VERSION 5.8 ;
BUSBITCHARS "[]" ;
DIVIDERCHAR "/" ;
UNITS
    DATABASE MICRONS 1000 ;
END UNITS

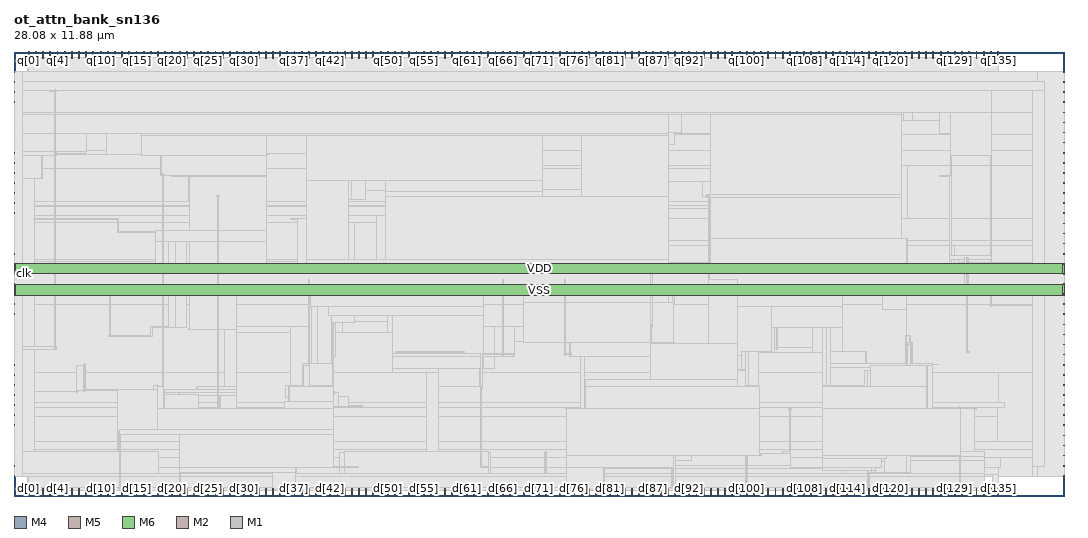
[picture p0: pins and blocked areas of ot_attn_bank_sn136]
MACRO ot_attn_bank_sn136
  FOREIGN ot_attn_bank_sn136 0 0 ;
  CLASS BLOCK ;
  SIZE 28.08 BY 11.88 ;
  PIN clk
    DIRECTION INPUT ;
    USE SIGNAL ;
    PORT
      LAYER M4 ;
        RECT  0 5.928 0.192 5.952 ;
    END
  END clk
  PIN d[0]
    DIRECTION INPUT ;
    USE SIGNAL ;
    PORT
      LAYER M5 ;
        RECT  0.384 0 0.408 0.192 ;
    END
  END d[0]
  PIN d[100]
    DIRECTION INPUT ;
    USE SIGNAL ;
    PORT
      LAYER M5 ;
        RECT  19.584 0 19.608 0.192 ;
    END
  END d[100]
  PIN d[101]
    DIRECTION INPUT ;
    USE SIGNAL ;
    PORT
      LAYER M5 ;
        RECT  19.776 0 19.8 0.192 ;
    END
  END d[101]
  PIN d[102]
    DIRECTION INPUT ;
    USE SIGNAL ;
    PORT
      LAYER M5 ;
        RECT  19.968 0 19.992 0.192 ;
    END
  END d[102]
  PIN d[103]
    DIRECTION INPUT ;
    USE SIGNAL ;
    PORT
      LAYER M5 ;
        RECT  20.16 0 20.184 0.192 ;
    END
  END d[103]
  PIN d[104]
    DIRECTION INPUT ;
    USE SIGNAL ;
    PORT
      LAYER M5 ;
        RECT  20.352 0 20.376 0.192 ;
    END
  END d[104]
  PIN d[105]
    DIRECTION INPUT ;
    USE SIGNAL ;
    PORT
      LAYER M5 ;
        RECT  20.544 0 20.568 0.192 ;
    END
  END d[105]
  PIN d[106]
    DIRECTION INPUT ;
    USE SIGNAL ;
    PORT
      LAYER M5 ;
        RECT  20.736 0 20.76 0.192 ;
    END
  END d[106]
  PIN d[107]
    DIRECTION INPUT ;
    USE SIGNAL ;
    PORT
      LAYER M5 ;
        RECT  20.928 0 20.952 0.192 ;
    END
  END d[107]
  PIN d[108]
    DIRECTION INPUT ;
    USE SIGNAL ;
    PORT
      LAYER M5 ;
        RECT  21.12 0 21.144 0.192 ;
    END
  END d[108]
  PIN d[109]
    DIRECTION INPUT ;
    USE SIGNAL ;
    PORT
      LAYER M5 ;
        RECT  21.312 0 21.336 0.192 ;
    END
  END d[109]
  PIN d[10]
    DIRECTION INPUT ;
    USE SIGNAL ;
    PORT
      LAYER M5 ;
        RECT  2.304 0 2.328 0.192 ;
    END
  END d[10]
  PIN d[110]
    DIRECTION INPUT ;
    USE SIGNAL ;
    PORT
      LAYER M5 ;
        RECT  21.504 0 21.528 0.192 ;
    END
  END d[110]
  PIN d[111]
    DIRECTION INPUT ;
    USE SIGNAL ;
    PORT
      LAYER M5 ;
        RECT  21.696 0 21.72 0.192 ;
    END
  END d[111]
  PIN d[112]
    DIRECTION INPUT ;
    USE SIGNAL ;
    PORT
      LAYER M5 ;
        RECT  21.888 0 21.912 0.192 ;
    END
  END d[112]
  PIN d[113]
    DIRECTION INPUT ;
    USE SIGNAL ;
    PORT
      LAYER M5 ;
        RECT  22.08 0 22.104 0.192 ;
    END
  END d[113]
  PIN d[114]
    DIRECTION INPUT ;
    USE SIGNAL ;
    PORT
      LAYER M5 ;
        RECT  22.272 0 22.296 0.192 ;
    END
  END d[114]
  PIN d[115]
    DIRECTION INPUT ;
    USE SIGNAL ;
    PORT
      LAYER M5 ;
        RECT  22.464 0 22.488 0.192 ;
    END
  END d[115]
  PIN d[116]
    DIRECTION INPUT ;
    USE SIGNAL ;
    PORT
      LAYER M5 ;
        RECT  22.656 0 22.68 0.192 ;
    END
  END d[116]
  PIN d[117]
    DIRECTION INPUT ;
    USE SIGNAL ;
    PORT
      LAYER M5 ;
        RECT  22.848 0 22.872 0.192 ;
    END
  END d[117]
  PIN d[118]
    DIRECTION INPUT ;
    USE SIGNAL ;
    PORT
      LAYER M5 ;
        RECT  23.04 0 23.064 0.192 ;
    END
  END d[118]
  PIN d[119]
    DIRECTION INPUT ;
    USE SIGNAL ;
    PORT
      LAYER M5 ;
        RECT  23.232 0 23.256 0.192 ;
    END
  END d[119]
  PIN d[11]
    DIRECTION INPUT ;
    USE SIGNAL ;
    PORT
      LAYER M5 ;
        RECT  2.496 0 2.52 0.192 ;
    END
  END d[11]
  PIN d[120]
    DIRECTION INPUT ;
    USE SIGNAL ;
    PORT
      LAYER M5 ;
        RECT  23.424 0 23.448 0.192 ;
    END
  END d[120]
  PIN d[121]
    DIRECTION INPUT ;
    USE SIGNAL ;
    PORT
      LAYER M5 ;
        RECT  23.616 0 23.64 0.192 ;
    END
  END d[121]
  PIN d[122]
    DIRECTION INPUT ;
    USE SIGNAL ;
    PORT
      LAYER M5 ;
        RECT  23.808 0 23.832 0.192 ;
    END
  END d[122]
  PIN d[123]
    DIRECTION INPUT ;
    USE SIGNAL ;
    PORT
      LAYER M5 ;
        RECT  24 0 24.024 0.192 ;
    END
  END d[123]
  PIN d[124]
    DIRECTION INPUT ;
    USE SIGNAL ;
    PORT
      LAYER M5 ;
        RECT  24.192 0 24.216 0.192 ;
    END
  END d[124]
  PIN d[125]
    DIRECTION INPUT ;
    USE SIGNAL ;
    PORT
      LAYER M5 ;
        RECT  24.384 0 24.408 0.192 ;
    END
  END d[125]
  PIN d[126]
    DIRECTION INPUT ;
    USE SIGNAL ;
    PORT
      LAYER M5 ;
        RECT  24.576 0 24.6 0.192 ;
    END
  END d[126]
  PIN d[127]
    DIRECTION INPUT ;
    USE SIGNAL ;
    PORT
      LAYER M5 ;
        RECT  24.768 0 24.792 0.192 ;
    END
  END d[127]
  PIN d[128]
    DIRECTION INPUT ;
    USE SIGNAL ;
    PORT
      LAYER M5 ;
        RECT  24.96 0 24.984 0.192 ;
    END
  END d[128]
  PIN d[129]
    DIRECTION INPUT ;
    USE SIGNAL ;
    PORT
      LAYER M5 ;
        RECT  25.152 0 25.176 0.192 ;
    END
  END d[129]
  PIN d[12]
    DIRECTION INPUT ;
    USE SIGNAL ;
    PORT
      LAYER M5 ;
        RECT  2.688 0 2.712 0.192 ;
    END
  END d[12]
  PIN d[130]
    DIRECTION INPUT ;
    USE SIGNAL ;
    PORT
      LAYER M5 ;
        RECT  25.344 0 25.368 0.192 ;
    END
  END d[130]
  PIN d[131]
    DIRECTION INPUT ;
    USE SIGNAL ;
    PORT
      LAYER M5 ;
        RECT  25.536 0 25.56 0.192 ;
    END
  END d[131]
  PIN d[132]
    DIRECTION INPUT ;
    USE SIGNAL ;
    PORT
      LAYER M5 ;
        RECT  25.728 0 25.752 0.192 ;
    END
  END d[132]
  PIN d[133]
    DIRECTION INPUT ;
    USE SIGNAL ;
    PORT
      LAYER M5 ;
        RECT  25.92 0 25.944 0.192 ;
    END
  END d[133]
  PIN d[134]
    DIRECTION INPUT ;
    USE SIGNAL ;
    PORT
      LAYER M5 ;
        RECT  26.112 0 26.136 0.192 ;
    END
  END d[134]
  PIN d[135]
    DIRECTION INPUT ;
    USE SIGNAL ;
    PORT
      LAYER M5 ;
        RECT  26.304 0 26.328 0.192 ;
    END
  END d[135]
  PIN d[13]
    DIRECTION INPUT ;
    USE SIGNAL ;
    PORT
      LAYER M5 ;
        RECT  2.88 0 2.904 0.192 ;
    END
  END d[13]
  PIN d[14]
    DIRECTION INPUT ;
    USE SIGNAL ;
    PORT
      LAYER M5 ;
        RECT  3.072 0 3.096 0.192 ;
    END
  END d[14]
  PIN d[15]
    DIRECTION INPUT ;
    USE SIGNAL ;
    PORT
      LAYER M5 ;
        RECT  3.264 0 3.288 0.192 ;
    END
  END d[15]
  PIN d[16]
    DIRECTION INPUT ;
    USE SIGNAL ;
    PORT
      LAYER M5 ;
        RECT  3.456 0 3.48 0.192 ;
    END
  END d[16]
  PIN d[17]
    DIRECTION INPUT ;
    USE SIGNAL ;
    PORT
      LAYER M5 ;
        RECT  3.648 0 3.672 0.192 ;
    END
  END d[17]
  PIN d[18]
    DIRECTION INPUT ;
    USE SIGNAL ;
    PORT
      LAYER M5 ;
        RECT  3.84 0 3.864 0.192 ;
    END
  END d[18]
  PIN d[19]
    DIRECTION INPUT ;
    USE SIGNAL ;
    PORT
      LAYER M5 ;
        RECT  4.032 0 4.056 0.192 ;
    END
  END d[19]
  PIN d[1]
    DIRECTION INPUT ;
    USE SIGNAL ;
    PORT
      LAYER M5 ;
        RECT  0.576 0 0.6 0.192 ;
    END
  END d[1]
  PIN d[20]
    DIRECTION INPUT ;
    USE SIGNAL ;
    PORT
      LAYER M5 ;
        RECT  4.224 0 4.248 0.192 ;
    END
  END d[20]
  PIN d[21]
    DIRECTION INPUT ;
    USE SIGNAL ;
    PORT
      LAYER M5 ;
        RECT  4.416 0 4.44 0.192 ;
    END
  END d[21]
  PIN d[22]
    DIRECTION INPUT ;
    USE SIGNAL ;
    PORT
      LAYER M5 ;
        RECT  4.608 0 4.632 0.192 ;
    END
  END d[22]
  PIN d[23]
    DIRECTION INPUT ;
    USE SIGNAL ;
    PORT
      LAYER M5 ;
        RECT  4.8 0 4.824 0.192 ;
    END
  END d[23]
  PIN d[24]
    DIRECTION INPUT ;
    USE SIGNAL ;
    PORT
      LAYER M5 ;
        RECT  4.992 0 5.016 0.192 ;
    END
  END d[24]
  PIN d[25]
    DIRECTION INPUT ;
    USE SIGNAL ;
    PORT
      LAYER M5 ;
        RECT  5.184 0 5.208 0.192 ;
    END
  END d[25]
  PIN d[26]
    DIRECTION INPUT ;
    USE SIGNAL ;
    PORT
      LAYER M5 ;
        RECT  5.376 0 5.4 0.192 ;
    END
  END d[26]
  PIN d[27]
    DIRECTION INPUT ;
    USE SIGNAL ;
    PORT
      LAYER M5 ;
        RECT  5.568 0 5.592 0.192 ;
    END
  END d[27]
  PIN d[28]
    DIRECTION INPUT ;
    USE SIGNAL ;
    PORT
      LAYER M5 ;
        RECT  5.76 0 5.784 0.192 ;
    END
  END d[28]
  PIN d[29]
    DIRECTION INPUT ;
    USE SIGNAL ;
    PORT
      LAYER M5 ;
        RECT  5.952 0 5.976 0.192 ;
    END
  END d[29]
  PIN d[2]
    DIRECTION INPUT ;
    USE SIGNAL ;
    PORT
      LAYER M5 ;
        RECT  0.768 0 0.792 0.192 ;
    END
  END d[2]
  PIN d[30]
    DIRECTION INPUT ;
    USE SIGNAL ;
    PORT
      LAYER M5 ;
        RECT  6.144 0 6.168 0.192 ;
    END
  END d[30]
  PIN d[31]
    DIRECTION INPUT ;
    USE SIGNAL ;
    PORT
      LAYER M5 ;
        RECT  6.336 0 6.36 0.192 ;
    END
  END d[31]
  PIN d[32]
    DIRECTION INPUT ;
    USE SIGNAL ;
    PORT
      LAYER M5 ;
        RECT  6.528 0 6.552 0.192 ;
    END
  END d[32]
  PIN d[33]
    DIRECTION INPUT ;
    USE SIGNAL ;
    PORT
      LAYER M5 ;
        RECT  6.72 0 6.744 0.192 ;
    END
  END d[33]
  PIN d[34]
    DIRECTION INPUT ;
    USE SIGNAL ;
    PORT
      LAYER M5 ;
        RECT  6.912 0 6.936 0.192 ;
    END
  END d[34]
  PIN d[35]
    DIRECTION INPUT ;
    USE SIGNAL ;
    PORT
      LAYER M5 ;
        RECT  7.104 0 7.128 0.192 ;
    END
  END d[35]
  PIN d[36]
    DIRECTION INPUT ;
    USE SIGNAL ;
    PORT
      LAYER M5 ;
        RECT  7.296 0 7.32 0.192 ;
    END
  END d[36]
  PIN d[37]
    DIRECTION INPUT ;
    USE SIGNAL ;
    PORT
      LAYER M5 ;
        RECT  7.488 0 7.512 0.192 ;
    END
  END d[37]
  PIN d[38]
    DIRECTION INPUT ;
    USE SIGNAL ;
    PORT
      LAYER M5 ;
        RECT  7.68 0 7.704 0.192 ;
    END
  END d[38]
  PIN d[39]
    DIRECTION INPUT ;
    USE SIGNAL ;
    PORT
      LAYER M5 ;
        RECT  7.872 0 7.896 0.192 ;
    END
  END d[39]
  PIN d[3]
    DIRECTION INPUT ;
    USE SIGNAL ;
    PORT
      LAYER M5 ;
        RECT  0.96 0 0.984 0.192 ;
    END
  END d[3]
  PIN d[40]
    DIRECTION INPUT ;
    USE SIGNAL ;
    PORT
      LAYER M5 ;
        RECT  8.064 0 8.088 0.192 ;
    END
  END d[40]
  PIN d[41]
    DIRECTION INPUT ;
    USE SIGNAL ;
    PORT
      LAYER M5 ;
        RECT  8.256 0 8.28 0.192 ;
    END
  END d[41]
  PIN d[42]
    DIRECTION INPUT ;
    USE SIGNAL ;
    PORT
      LAYER M5 ;
        RECT  8.448 0 8.472 0.192 ;
    END
  END d[42]
  PIN d[43]
    DIRECTION INPUT ;
    USE SIGNAL ;
    PORT
      LAYER M5 ;
        RECT  8.64 0 8.664 0.192 ;
    END
  END d[43]
  PIN d[44]
    DIRECTION INPUT ;
    USE SIGNAL ;
    PORT
      LAYER M5 ;
        RECT  8.832 0 8.856 0.192 ;
    END
  END d[44]
  PIN d[45]
    DIRECTION INPUT ;
    USE SIGNAL ;
    PORT
      LAYER M5 ;
        RECT  9.024 0 9.048 0.192 ;
    END
  END d[45]
  PIN d[46]
    DIRECTION INPUT ;
    USE SIGNAL ;
    PORT
      LAYER M5 ;
        RECT  9.216 0 9.24 0.192 ;
    END
  END d[46]
  PIN d[47]
    DIRECTION INPUT ;
    USE SIGNAL ;
    PORT
      LAYER M5 ;
        RECT  9.408 0 9.432 0.192 ;
    END
  END d[47]
  PIN d[48]
    DIRECTION INPUT ;
    USE SIGNAL ;
    PORT
      LAYER M5 ;
        RECT  9.6 0 9.624 0.192 ;
    END
  END d[48]
  PIN d[49]
    DIRECTION INPUT ;
    USE SIGNAL ;
    PORT
      LAYER M5 ;
        RECT  9.792 0 9.816 0.192 ;
    END
  END d[49]
  PIN d[4]
    DIRECTION INPUT ;
    USE SIGNAL ;
    PORT
      LAYER M5 ;
        RECT  1.152 0 1.176 0.192 ;
    END
  END d[4]
  PIN d[50]
    DIRECTION INPUT ;
    USE SIGNAL ;
    PORT
      LAYER M5 ;
        RECT  9.984 0 10.008 0.192 ;
    END
  END d[50]
  PIN d[51]
    DIRECTION INPUT ;
    USE SIGNAL ;
    PORT
      LAYER M5 ;
        RECT  10.176 0 10.2 0.192 ;
    END
  END d[51]
  PIN d[52]
    DIRECTION INPUT ;
    USE SIGNAL ;
    PORT
      LAYER M5 ;
        RECT  10.368 0 10.392 0.192 ;
    END
  END d[52]
  PIN d[53]
    DIRECTION INPUT ;
    USE SIGNAL ;
    PORT
      LAYER M5 ;
        RECT  10.56 0 10.584 0.192 ;
    END
  END d[53]
  PIN d[54]
    DIRECTION INPUT ;
    USE SIGNAL ;
    PORT
      LAYER M5 ;
        RECT  10.752 0 10.776 0.192 ;
    END
  END d[54]
  PIN d[55]
    DIRECTION INPUT ;
    USE SIGNAL ;
    PORT
      LAYER M5 ;
        RECT  10.944 0 10.968 0.192 ;
    END
  END d[55]
  PIN d[56]
    DIRECTION INPUT ;
    USE SIGNAL ;
    PORT
      LAYER M5 ;
        RECT  11.136 0 11.16 0.192 ;
    END
  END d[56]
  PIN d[57]
    DIRECTION INPUT ;
    USE SIGNAL ;
    PORT
      LAYER M5 ;
        RECT  11.328 0 11.352 0.192 ;
    END
  END d[57]
  PIN d[58]
    DIRECTION INPUT ;
    USE SIGNAL ;
    PORT
      LAYER M5 ;
        RECT  11.52 0 11.544 0.192 ;
    END
  END d[58]
  PIN d[59]
    DIRECTION INPUT ;
    USE SIGNAL ;
    PORT
      LAYER M5 ;
        RECT  11.712 0 11.736 0.192 ;
    END
  END d[59]
  PIN d[5]
    DIRECTION INPUT ;
    USE SIGNAL ;
    PORT
      LAYER M5 ;
        RECT  1.344 0 1.368 0.192 ;
    END
  END d[5]
  PIN d[60]
    DIRECTION INPUT ;
    USE SIGNAL ;
    PORT
      LAYER M5 ;
        RECT  11.904 0 11.928 0.192 ;
    END
  END d[60]
  PIN d[61]
    DIRECTION INPUT ;
    USE SIGNAL ;
    PORT
      LAYER M5 ;
        RECT  12.096 0 12.12 0.192 ;
    END
  END d[61]
  PIN d[62]
    DIRECTION INPUT ;
    USE SIGNAL ;
    PORT
      LAYER M5 ;
        RECT  12.288 0 12.312 0.192 ;
    END
  END d[62]
  PIN d[63]
    DIRECTION INPUT ;
    USE SIGNAL ;
    PORT
      LAYER M5 ;
        RECT  12.48 0 12.504 0.192 ;
    END
  END d[63]
  PIN d[64]
    DIRECTION INPUT ;
    USE SIGNAL ;
    PORT
      LAYER M5 ;
        RECT  12.672 0 12.696 0.192 ;
    END
  END d[64]
  PIN d[65]
    DIRECTION INPUT ;
    USE SIGNAL ;
    PORT
      LAYER M5 ;
        RECT  12.864 0 12.888 0.192 ;
    END
  END d[65]
  PIN d[66]
    DIRECTION INPUT ;
    USE SIGNAL ;
    PORT
      LAYER M5 ;
        RECT  13.056 0 13.08 0.192 ;
    END
  END d[66]
  PIN d[67]
    DIRECTION INPUT ;
    USE SIGNAL ;
    PORT
      LAYER M5 ;
        RECT  13.248 0 13.272 0.192 ;
    END
  END d[67]
  PIN d[68]
    DIRECTION INPUT ;
    USE SIGNAL ;
    PORT
      LAYER M5 ;
        RECT  13.44 0 13.464 0.192 ;
    END
  END d[68]
  PIN d[69]
    DIRECTION INPUT ;
    USE SIGNAL ;
    PORT
      LAYER M5 ;
        RECT  13.632 0 13.656 0.192 ;
    END
  END d[69]
  PIN d[6]
    DIRECTION INPUT ;
    USE SIGNAL ;
    PORT
      LAYER M5 ;
        RECT  1.536 0 1.56 0.192 ;
    END
  END d[6]
  PIN d[70]
    DIRECTION INPUT ;
    USE SIGNAL ;
    PORT
      LAYER M5 ;
        RECT  13.824 0 13.848 0.192 ;
    END
  END d[70]
  PIN d[71]
    DIRECTION INPUT ;
    USE SIGNAL ;
    PORT
      LAYER M5 ;
        RECT  14.016 0 14.04 0.192 ;
    END
  END d[71]
  PIN d[72]
    DIRECTION INPUT ;
    USE SIGNAL ;
    PORT
      LAYER M5 ;
        RECT  14.208 0 14.232 0.192 ;
    END
  END d[72]
  PIN d[73]
    DIRECTION INPUT ;
    USE SIGNAL ;
    PORT
      LAYER M5 ;
        RECT  14.4 0 14.424 0.192 ;
    END
  END d[73]
  PIN d[74]
    DIRECTION INPUT ;
    USE SIGNAL ;
    PORT
      LAYER M5 ;
        RECT  14.592 0 14.616 0.192 ;
    END
  END d[74]
  PIN d[75]
    DIRECTION INPUT ;
    USE SIGNAL ;
    PORT
      LAYER M5 ;
        RECT  14.784 0 14.808 0.192 ;
    END
  END d[75]
  PIN d[76]
    DIRECTION INPUT ;
    USE SIGNAL ;
    PORT
      LAYER M5 ;
        RECT  14.976 0 15 0.192 ;
    END
  END d[76]
  PIN d[77]
    DIRECTION INPUT ;
    USE SIGNAL ;
    PORT
      LAYER M5 ;
        RECT  15.168 0 15.192 0.192 ;
    END
  END d[77]
  PIN d[78]
    DIRECTION INPUT ;
    USE SIGNAL ;
    PORT
      LAYER M5 ;
        RECT  15.36 0 15.384 0.192 ;
    END
  END d[78]
  PIN d[79]
    DIRECTION INPUT ;
    USE SIGNAL ;
    PORT
      LAYER M5 ;
        RECT  15.552 0 15.576 0.192 ;
    END
  END d[79]
  PIN d[7]
    DIRECTION INPUT ;
    USE SIGNAL ;
    PORT
      LAYER M5 ;
        RECT  1.728 0 1.752 0.192 ;
    END
  END d[7]
  PIN d[80]
    DIRECTION INPUT ;
    USE SIGNAL ;
    PORT
      LAYER M5 ;
        RECT  15.744 0 15.768 0.192 ;
    END
  END d[80]
  PIN d[81]
    DIRECTION INPUT ;
    USE SIGNAL ;
    PORT
      LAYER M5 ;
        RECT  15.936 0 15.96 0.192 ;
    END
  END d[81]
  PIN d[82]
    DIRECTION INPUT ;
    USE SIGNAL ;
    PORT
      LAYER M5 ;
        RECT  16.128 0 16.152 0.192 ;
    END
  END d[82]
  PIN d[83]
    DIRECTION INPUT ;
    USE SIGNAL ;
    PORT
      LAYER M5 ;
        RECT  16.32 0 16.344 0.192 ;
    END
  END d[83]
  PIN d[84]
    DIRECTION INPUT ;
    USE SIGNAL ;
    PORT
      LAYER M5 ;
        RECT  16.512 0 16.536 0.192 ;
    END
  END d[84]
  PIN d[85]
    DIRECTION INPUT ;
    USE SIGNAL ;
    PORT
      LAYER M5 ;
        RECT  16.704 0 16.728 0.192 ;
    END
  END d[85]
  PIN d[86]
    DIRECTION INPUT ;
    USE SIGNAL ;
    PORT
      LAYER M5 ;
        RECT  16.896 0 16.92 0.192 ;
    END
  END d[86]
  PIN d[87]
    DIRECTION INPUT ;
    USE SIGNAL ;
    PORT
      LAYER M5 ;
        RECT  17.088 0 17.112 0.192 ;
    END
  END d[87]
  PIN d[88]
    DIRECTION INPUT ;
    USE SIGNAL ;
    PORT
      LAYER M5 ;
        RECT  17.28 0 17.304 0.192 ;
    END
  END d[88]
  PIN d[89]
    DIRECTION INPUT ;
    USE SIGNAL ;
    PORT
      LAYER M5 ;
        RECT  17.472 0 17.496 0.192 ;
    END
  END d[89]
  PIN d[8]
    DIRECTION INPUT ;
    USE SIGNAL ;
    PORT
      LAYER M5 ;
        RECT  1.92 0 1.944 0.192 ;
    END
  END d[8]
  PIN d[90]
    DIRECTION INPUT ;
    USE SIGNAL ;
    PORT
      LAYER M5 ;
        RECT  17.664 0 17.688 0.192 ;
    END
  END d[90]
  PIN d[91]
    DIRECTION INPUT ;
    USE SIGNAL ;
    PORT
      LAYER M5 ;
        RECT  17.856 0 17.88 0.192 ;
    END
  END d[91]
  PIN d[92]
    DIRECTION INPUT ;
    USE SIGNAL ;
    PORT
      LAYER M5 ;
        RECT  18.048 0 18.072 0.192 ;
    END
  END d[92]
  PIN d[93]
    DIRECTION INPUT ;
    USE SIGNAL ;
    PORT
      LAYER M5 ;
        RECT  18.24 0 18.264 0.192 ;
    END
  END d[93]
  PIN d[94]
    DIRECTION INPUT ;
    USE SIGNAL ;
    PORT
      LAYER M5 ;
        RECT  18.432 0 18.456 0.192 ;
    END
  END d[94]
  PIN d[95]
    DIRECTION INPUT ;
    USE SIGNAL ;
    PORT
      LAYER M5 ;
        RECT  18.624 0 18.648 0.192 ;
    END
  END d[95]
  PIN d[96]
    DIRECTION INPUT ;
    USE SIGNAL ;
    PORT
      LAYER M5 ;
        RECT  18.816 0 18.84 0.192 ;
    END
  END d[96]
  PIN d[97]
    DIRECTION INPUT ;
    USE SIGNAL ;
    PORT
      LAYER M5 ;
        RECT  19.008 0 19.032 0.192 ;
    END
  END d[97]
  PIN d[98]
    DIRECTION INPUT ;
    USE SIGNAL ;
    PORT
      LAYER M5 ;
        RECT  19.2 0 19.224 0.192 ;
    END
  END d[98]
  PIN d[99]
    DIRECTION INPUT ;
    USE SIGNAL ;
    PORT
      LAYER M5 ;
        RECT  19.392 0 19.416 0.192 ;
    END
  END d[99]
  PIN d[9]
    DIRECTION INPUT ;
    USE SIGNAL ;
    PORT
      LAYER M5 ;
        RECT  2.112 0 2.136 0.192 ;
    END
  END d[9]
  PIN q[0]
    DIRECTION OUTPUT ;
    USE SIGNAL ;
    PORT
      LAYER M5 ;
        RECT  0.384 11.688 0.408 11.88 ;
    END
  END q[0]
  PIN q[100]
    DIRECTION OUTPUT ;
    USE SIGNAL ;
    PORT
      LAYER M5 ;
        RECT  19.584 11.688 19.608 11.88 ;
    END
  END q[100]
  PIN q[101]
    DIRECTION OUTPUT ;
    USE SIGNAL ;
    PORT
      LAYER M5 ;
        RECT  19.776 11.688 19.8 11.88 ;
    END
  END q[101]
  PIN q[102]
    DIRECTION OUTPUT ;
    USE SIGNAL ;
    PORT
      LAYER M5 ;
        RECT  19.968 11.688 19.992 11.88 ;
    END
  END q[102]
  PIN q[103]
    DIRECTION OUTPUT ;
    USE SIGNAL ;
    PORT
      LAYER M5 ;
        RECT  20.16 11.688 20.184 11.88 ;
    END
  END q[103]
  PIN q[104]
    DIRECTION OUTPUT ;
    USE SIGNAL ;
    PORT
      LAYER M5 ;
        RECT  20.352 11.688 20.376 11.88 ;
    END
  END q[104]
  PIN q[105]
    DIRECTION OUTPUT ;
    USE SIGNAL ;
    PORT
      LAYER M5 ;
        RECT  20.544 11.688 20.568 11.88 ;
    END
  END q[105]
  PIN q[106]
    DIRECTION OUTPUT ;
    USE SIGNAL ;
    PORT
      LAYER M5 ;
        RECT  20.736 11.688 20.76 11.88 ;
    END
  END q[106]
  PIN q[107]
    DIRECTION OUTPUT ;
    USE SIGNAL ;
    PORT
      LAYER M5 ;
        RECT  20.928 11.688 20.952 11.88 ;
    END
  END q[107]
  PIN q[108]
    DIRECTION OUTPUT ;
    USE SIGNAL ;
    PORT
      LAYER M5 ;
        RECT  21.12 11.688 21.144 11.88 ;
    END
  END q[108]
  PIN q[109]
    DIRECTION OUTPUT ;
    USE SIGNAL ;
    PORT
      LAYER M5 ;
        RECT  21.312 11.688 21.336 11.88 ;
    END
  END q[109]
  PIN q[10]
    DIRECTION OUTPUT ;
    USE SIGNAL ;
    PORT
      LAYER M5 ;
        RECT  2.304 11.688 2.328 11.88 ;
    END
  END q[10]
  PIN q[110]
    DIRECTION OUTPUT ;
    USE SIGNAL ;
    PORT
      LAYER M5 ;
        RECT  21.504 11.688 21.528 11.88 ;
    END
  END q[110]
  PIN q[111]
    DIRECTION OUTPUT ;
    USE SIGNAL ;
    PORT
      LAYER M5 ;
        RECT  21.696 11.688 21.72 11.88 ;
    END
  END q[111]
  PIN q[112]
    DIRECTION OUTPUT ;
    USE SIGNAL ;
    PORT
      LAYER M5 ;
        RECT  21.888 11.688 21.912 11.88 ;
    END
  END q[112]
  PIN q[113]
    DIRECTION OUTPUT ;
    USE SIGNAL ;
    PORT
      LAYER M5 ;
        RECT  22.08 11.688 22.104 11.88 ;
    END
  END q[113]
  PIN q[114]
    DIRECTION OUTPUT ;
    USE SIGNAL ;
    PORT
      LAYER M5 ;
        RECT  22.272 11.688 22.296 11.88 ;
    END
  END q[114]
  PIN q[115]
    DIRECTION OUTPUT ;
    USE SIGNAL ;
    PORT
      LAYER M5 ;
        RECT  22.464 11.688 22.488 11.88 ;
    END
  END q[115]
  PIN q[116]
    DIRECTION OUTPUT ;
    USE SIGNAL ;
    PORT
      LAYER M5 ;
        RECT  22.656 11.688 22.68 11.88 ;
    END
  END q[116]
  PIN q[117]
    DIRECTION OUTPUT ;
    USE SIGNAL ;
    PORT
      LAYER M5 ;
        RECT  22.848 11.688 22.872 11.88 ;
    END
  END q[117]
  PIN q[118]
    DIRECTION OUTPUT ;
    USE SIGNAL ;
    PORT
      LAYER M5 ;
        RECT  23.04 11.688 23.064 11.88 ;
    END
  END q[118]
  PIN q[119]
    DIRECTION OUTPUT ;
    USE SIGNAL ;
    PORT
      LAYER M5 ;
        RECT  23.232 11.688 23.256 11.88 ;
    END
  END q[119]
  PIN q[11]
    DIRECTION OUTPUT ;
    USE SIGNAL ;
    PORT
      LAYER M5 ;
        RECT  2.496 11.688 2.52 11.88 ;
    END
  END q[11]
  PIN q[120]
    DIRECTION OUTPUT ;
    USE SIGNAL ;
    PORT
      LAYER M5 ;
        RECT  23.424 11.688 23.448 11.88 ;
    END
  END q[120]
  PIN q[121]
    DIRECTION OUTPUT ;
    USE SIGNAL ;
    PORT
      LAYER M5 ;
        RECT  23.616 11.688 23.64 11.88 ;
    END
  END q[121]
  PIN q[122]
    DIRECTION OUTPUT ;
    USE SIGNAL ;
    PORT
      LAYER M5 ;
        RECT  23.808 11.688 23.832 11.88 ;
    END
  END q[122]
  PIN q[123]
    DIRECTION OUTPUT ;
    USE SIGNAL ;
    PORT
      LAYER M5 ;
        RECT  24 11.688 24.024 11.88 ;
    END
  END q[123]
  PIN q[124]
    DIRECTION OUTPUT ;
    USE SIGNAL ;
    PORT
      LAYER M5 ;
        RECT  24.192 11.688 24.216 11.88 ;
    END
  END q[124]
  PIN q[125]
    DIRECTION OUTPUT ;
    USE SIGNAL ;
    PORT
      LAYER M5 ;
        RECT  24.384 11.688 24.408 11.88 ;
    END
  END q[125]
  PIN q[126]
    DIRECTION OUTPUT ;
    USE SIGNAL ;
    PORT
      LAYER M5 ;
        RECT  24.576 11.688 24.6 11.88 ;
    END
  END q[126]
  PIN q[127]
    DIRECTION OUTPUT ;
    USE SIGNAL ;
    PORT
      LAYER M5 ;
        RECT  24.768 11.688 24.792 11.88 ;
    END
  END q[127]
  PIN q[128]
    DIRECTION OUTPUT ;
    USE SIGNAL ;
    PORT
      LAYER M5 ;
        RECT  24.96 11.688 24.984 11.88 ;
    END
  END q[128]
  PIN q[129]
    DIRECTION OUTPUT ;
    USE SIGNAL ;
    PORT
      LAYER M5 ;
        RECT  25.152 11.688 25.176 11.88 ;
    END
  END q[129]
  PIN q[12]
    DIRECTION OUTPUT ;
    USE SIGNAL ;
    PORT
      LAYER M5 ;
        RECT  2.688 11.688 2.712 11.88 ;
    END
  END q[12]
  PIN q[130]
    DIRECTION OUTPUT ;
    USE SIGNAL ;
    PORT
      LAYER M5 ;
        RECT  25.344 11.688 25.368 11.88 ;
    END
  END q[130]
  PIN q[131]
    DIRECTION OUTPUT ;
    USE SIGNAL ;
    PORT
      LAYER M5 ;
        RECT  25.536 11.688 25.56 11.88 ;
    END
  END q[131]
  PIN q[132]
    DIRECTION OUTPUT ;
    USE SIGNAL ;
    PORT
      LAYER M5 ;
        RECT  25.728 11.688 25.752 11.88 ;
    END
  END q[132]
  PIN q[133]
    DIRECTION OUTPUT ;
    USE SIGNAL ;
    PORT
      LAYER M5 ;
        RECT  25.92 11.688 25.944 11.88 ;
    END
  END q[133]
  PIN q[134]
    DIRECTION OUTPUT ;
    USE SIGNAL ;
    PORT
      LAYER M5 ;
        RECT  26.112 11.688 26.136 11.88 ;
    END
  END q[134]
  PIN q[135]
    DIRECTION OUTPUT ;
    USE SIGNAL ;
    PORT
      LAYER M5 ;
        RECT  26.304 11.688 26.328 11.88 ;
    END
  END q[135]
  PIN q[13]
    DIRECTION OUTPUT ;
    USE SIGNAL ;
    PORT
      LAYER M5 ;
        RECT  2.88 11.688 2.904 11.88 ;
    END
  END q[13]
  PIN q[14]
    DIRECTION OUTPUT ;
    USE SIGNAL ;
    PORT
      LAYER M5 ;
        RECT  3.072 11.688 3.096 11.88 ;
    END
  END q[14]
  PIN q[15]
    DIRECTION OUTPUT ;
    USE SIGNAL ;
    PORT
      LAYER M5 ;
        RECT  3.264 11.688 3.288 11.88 ;
    END
  END q[15]
  PIN q[16]
    DIRECTION OUTPUT ;
    USE SIGNAL ;
    PORT
      LAYER M5 ;
        RECT  3.456 11.688 3.48 11.88 ;
    END
  END q[16]
  PIN q[17]
    DIRECTION OUTPUT ;
    USE SIGNAL ;
    PORT
      LAYER M5 ;
        RECT  3.648 11.688 3.672 11.88 ;
    END
  END q[17]
  PIN q[18]
    DIRECTION OUTPUT ;
    USE SIGNAL ;
    PORT
      LAYER M5 ;
        RECT  3.84 11.688 3.864 11.88 ;
    END
  END q[18]
  PIN q[19]
    DIRECTION OUTPUT ;
    USE SIGNAL ;
    PORT
      LAYER M5 ;
        RECT  4.032 11.688 4.056 11.88 ;
    END
  END q[19]
  PIN q[1]
    DIRECTION OUTPUT ;
    USE SIGNAL ;
    PORT
      LAYER M5 ;
        RECT  0.576 11.688 0.6 11.88 ;
    END
  END q[1]
  PIN q[20]
    DIRECTION OUTPUT ;
    USE SIGNAL ;
    PORT
      LAYER M5 ;
        RECT  4.224 11.688 4.248 11.88 ;
    END
  END q[20]
  PIN q[21]
    DIRECTION OUTPUT ;
    USE SIGNAL ;
    PORT
      LAYER M5 ;
        RECT  4.416 11.688 4.44 11.88 ;
    END
  END q[21]
  PIN q[22]
    DIRECTION OUTPUT ;
    USE SIGNAL ;
    PORT
      LAYER M5 ;
        RECT  4.608 11.688 4.632 11.88 ;
    END
  END q[22]
  PIN q[23]
    DIRECTION OUTPUT ;
    USE SIGNAL ;
    PORT
      LAYER M5 ;
        RECT  4.8 11.688 4.824 11.88 ;
    END
  END q[23]
  PIN q[24]
    DIRECTION OUTPUT ;
    USE SIGNAL ;
    PORT
      LAYER M5 ;
        RECT  4.992 11.688 5.016 11.88 ;
    END
  END q[24]
  PIN q[25]
    DIRECTION OUTPUT ;
    USE SIGNAL ;
    PORT
      LAYER M5 ;
        RECT  5.184 11.688 5.208 11.88 ;
    END
  END q[25]
  PIN q[26]
    DIRECTION OUTPUT ;
    USE SIGNAL ;
    PORT
      LAYER M5 ;
        RECT  5.376 11.688 5.4 11.88 ;
    END
  END q[26]
  PIN q[27]
    DIRECTION OUTPUT ;
    USE SIGNAL ;
    PORT
      LAYER M5 ;
        RECT  5.568 11.688 5.592 11.88 ;
    END
  END q[27]
  PIN q[28]
    DIRECTION OUTPUT ;
    USE SIGNAL ;
    PORT
      LAYER M5 ;
        RECT  5.76 11.688 5.784 11.88 ;
    END
  END q[28]
  PIN q[29]
    DIRECTION OUTPUT ;
    USE SIGNAL ;
    PORT
      LAYER M5 ;
        RECT  5.952 11.688 5.976 11.88 ;
    END
  END q[29]
  PIN q[2]
    DIRECTION OUTPUT ;
    USE SIGNAL ;
    PORT
      LAYER M5 ;
        RECT  0.768 11.688 0.792 11.88 ;
    END
  END q[2]
  PIN q[30]
    DIRECTION OUTPUT ;
    USE SIGNAL ;
    PORT
      LAYER M5 ;
        RECT  6.144 11.688 6.168 11.88 ;
    END
  END q[30]
  PIN q[31]
    DIRECTION OUTPUT ;
    USE SIGNAL ;
    PORT
      LAYER M5 ;
        RECT  6.336 11.688 6.36 11.88 ;
    END
  END q[31]
  PIN q[32]
    DIRECTION OUTPUT ;
    USE SIGNAL ;
    PORT
      LAYER M5 ;
        RECT  6.528 11.688 6.552 11.88 ;
    END
  END q[32]
  PIN q[33]
    DIRECTION OUTPUT ;
    USE SIGNAL ;
    PORT
      LAYER M5 ;
        RECT  6.72 11.688 6.744 11.88 ;
    END
  END q[33]
  PIN q[34]
    DIRECTION OUTPUT ;
    USE SIGNAL ;
    PORT
      LAYER M5 ;
        RECT  6.912 11.688 6.936 11.88 ;
    END
  END q[34]
  PIN q[35]
    DIRECTION OUTPUT ;
    USE SIGNAL ;
    PORT
      LAYER M5 ;
        RECT  7.104 11.688 7.128 11.88 ;
    END
  END q[35]
  PIN q[36]
    DIRECTION OUTPUT ;
    USE SIGNAL ;
    PORT
      LAYER M5 ;
        RECT  7.296 11.688 7.32 11.88 ;
    END
  END q[36]
  PIN q[37]
    DIRECTION OUTPUT ;
    USE SIGNAL ;
    PORT
      LAYER M5 ;
        RECT  7.488 11.688 7.512 11.88 ;
    END
  END q[37]
  PIN q[38]
    DIRECTION OUTPUT ;
    USE SIGNAL ;
    PORT
      LAYER M5 ;
        RECT  7.68 11.688 7.704 11.88 ;
    END
  END q[38]
  PIN q[39]
    DIRECTION OUTPUT ;
    USE SIGNAL ;
    PORT
      LAYER M5 ;
        RECT  7.872 11.688 7.896 11.88 ;
    END
  END q[39]
  PIN q[3]
    DIRECTION OUTPUT ;
    USE SIGNAL ;
    PORT
      LAYER M5 ;
        RECT  0.96 11.688 0.984 11.88 ;
    END
  END q[3]
  PIN q[40]
    DIRECTION OUTPUT ;
    USE SIGNAL ;
    PORT
      LAYER M5 ;
        RECT  8.064 11.688 8.088 11.88 ;
    END
  END q[40]
  PIN q[41]
    DIRECTION OUTPUT ;
    USE SIGNAL ;
    PORT
      LAYER M5 ;
        RECT  8.256 11.688 8.28 11.88 ;
    END
  END q[41]
  PIN q[42]
    DIRECTION OUTPUT ;
    USE SIGNAL ;
    PORT
      LAYER M5 ;
        RECT  8.448 11.688 8.472 11.88 ;
    END
  END q[42]
  PIN q[43]
    DIRECTION OUTPUT ;
    USE SIGNAL ;
    PORT
      LAYER M5 ;
        RECT  8.64 11.688 8.664 11.88 ;
    END
  END q[43]
  PIN q[44]
    DIRECTION OUTPUT ;
    USE SIGNAL ;
    PORT
      LAYER M5 ;
        RECT  8.832 11.688 8.856 11.88 ;
    END
  END q[44]
  PIN q[45]
    DIRECTION OUTPUT ;
    USE SIGNAL ;
    PORT
      LAYER M5 ;
        RECT  9.024 11.688 9.048 11.88 ;
    END
  END q[45]
  PIN q[46]
    DIRECTION OUTPUT ;
    USE SIGNAL ;
    PORT
      LAYER M5 ;
        RECT  9.216 11.688 9.24 11.88 ;
    END
  END q[46]
  PIN q[47]
    DIRECTION OUTPUT ;
    USE SIGNAL ;
    PORT
      LAYER M5 ;
        RECT  9.408 11.688 9.432 11.88 ;
    END
  END q[47]
  PIN q[48]
    DIRECTION OUTPUT ;
    USE SIGNAL ;
    PORT
      LAYER M5 ;
        RECT  9.6 11.688 9.624 11.88 ;
    END
  END q[48]
  PIN q[49]
    DIRECTION OUTPUT ;
    USE SIGNAL ;
    PORT
      LAYER M5 ;
        RECT  9.792 11.688 9.816 11.88 ;
    END
  END q[49]
  PIN q[4]
    DIRECTION OUTPUT ;
    USE SIGNAL ;
    PORT
      LAYER M5 ;
        RECT  1.152 11.688 1.176 11.88 ;
    END
  END q[4]
  PIN q[50]
    DIRECTION OUTPUT ;
    USE SIGNAL ;
    PORT
      LAYER M5 ;
        RECT  9.984 11.688 10.008 11.88 ;
    END
  END q[50]
  PIN q[51]
    DIRECTION OUTPUT ;
    USE SIGNAL ;
    PORT
      LAYER M5 ;
        RECT  10.176 11.688 10.2 11.88 ;
    END
  END q[51]
  PIN q[52]
    DIRECTION OUTPUT ;
    USE SIGNAL ;
    PORT
      LAYER M5 ;
        RECT  10.368 11.688 10.392 11.88 ;
    END
  END q[52]
  PIN q[53]
    DIRECTION OUTPUT ;
    USE SIGNAL ;
    PORT
      LAYER M5 ;
        RECT  10.56 11.688 10.584 11.88 ;
    END
  END q[53]
  PIN q[54]
    DIRECTION OUTPUT ;
    USE SIGNAL ;
    PORT
      LAYER M5 ;
        RECT  10.752 11.688 10.776 11.88 ;
    END
  END q[54]
  PIN q[55]
    DIRECTION OUTPUT ;
    USE SIGNAL ;
    PORT
      LAYER M5 ;
        RECT  10.944 11.688 10.968 11.88 ;
    END
  END q[55]
  PIN q[56]
    DIRECTION OUTPUT ;
    USE SIGNAL ;
    PORT
      LAYER M5 ;
        RECT  11.136 11.688 11.16 11.88 ;
    END
  END q[56]
  PIN q[57]
    DIRECTION OUTPUT ;
    USE SIGNAL ;
    PORT
      LAYER M5 ;
        RECT  11.328 11.688 11.352 11.88 ;
    END
  END q[57]
  PIN q[58]
    DIRECTION OUTPUT ;
    USE SIGNAL ;
    PORT
      LAYER M5 ;
        RECT  11.52 11.688 11.544 11.88 ;
    END
  END q[58]
  PIN q[59]
    DIRECTION OUTPUT ;
    USE SIGNAL ;
    PORT
      LAYER M5 ;
        RECT  11.712 11.688 11.736 11.88 ;
    END
  END q[59]
  PIN q[5]
    DIRECTION OUTPUT ;
    USE SIGNAL ;
    PORT
      LAYER M5 ;
        RECT  1.344 11.688 1.368 11.88 ;
    END
  END q[5]
  PIN q[60]
    DIRECTION OUTPUT ;
    USE SIGNAL ;
    PORT
      LAYER M5 ;
        RECT  11.904 11.688 11.928 11.88 ;
    END
  END q[60]
  PIN q[61]
    DIRECTION OUTPUT ;
    USE SIGNAL ;
    PORT
      LAYER M5 ;
        RECT  12.096 11.688 12.12 11.88 ;
    END
  END q[61]
  PIN q[62]
    DIRECTION OUTPUT ;
    USE SIGNAL ;
    PORT
      LAYER M5 ;
        RECT  12.288 11.688 12.312 11.88 ;
    END
  END q[62]
  PIN q[63]
    DIRECTION OUTPUT ;
    USE SIGNAL ;
    PORT
      LAYER M5 ;
        RECT  12.48 11.688 12.504 11.88 ;
    END
  END q[63]
  PIN q[64]
    DIRECTION OUTPUT ;
    USE SIGNAL ;
    PORT
      LAYER M5 ;
        RECT  12.672 11.688 12.696 11.88 ;
    END
  END q[64]
  PIN q[65]
    DIRECTION OUTPUT ;
    USE SIGNAL ;
    PORT
      LAYER M5 ;
        RECT  12.864 11.688 12.888 11.88 ;
    END
  END q[65]
  PIN q[66]
    DIRECTION OUTPUT ;
    USE SIGNAL ;
    PORT
      LAYER M5 ;
        RECT  13.056 11.688 13.08 11.88 ;
    END
  END q[66]
  PIN q[67]
    DIRECTION OUTPUT ;
    USE SIGNAL ;
    PORT
      LAYER M5 ;
        RECT  13.248 11.688 13.272 11.88 ;
    END
  END q[67]
  PIN q[68]
    DIRECTION OUTPUT ;
    USE SIGNAL ;
    PORT
      LAYER M5 ;
        RECT  13.44 11.688 13.464 11.88 ;
    END
  END q[68]
  PIN q[69]
    DIRECTION OUTPUT ;
    USE SIGNAL ;
    PORT
      LAYER M5 ;
        RECT  13.632 11.688 13.656 11.88 ;
    END
  END q[69]
  PIN q[6]
    DIRECTION OUTPUT ;
    USE SIGNAL ;
    PORT
      LAYER M5 ;
        RECT  1.536 11.688 1.56 11.88 ;
    END
  END q[6]
  PIN q[70]
    DIRECTION OUTPUT ;
    USE SIGNAL ;
    PORT
      LAYER M5 ;
        RECT  13.824 11.688 13.848 11.88 ;
    END
  END q[70]
  PIN q[71]
    DIRECTION OUTPUT ;
    USE SIGNAL ;
    PORT
      LAYER M5 ;
        RECT  14.016 11.688 14.04 11.88 ;
    END
  END q[71]
  PIN q[72]
    DIRECTION OUTPUT ;
    USE SIGNAL ;
    PORT
      LAYER M5 ;
        RECT  14.208 11.688 14.232 11.88 ;
    END
  END q[72]
  PIN q[73]
    DIRECTION OUTPUT ;
    USE SIGNAL ;
    PORT
      LAYER M5 ;
        RECT  14.4 11.688 14.424 11.88 ;
    END
  END q[73]
  PIN q[74]
    DIRECTION OUTPUT ;
    USE SIGNAL ;
    PORT
      LAYER M5 ;
        RECT  14.592 11.688 14.616 11.88 ;
    END
  END q[74]
  PIN q[75]
    DIRECTION OUTPUT ;
    USE SIGNAL ;
    PORT
      LAYER M5 ;
        RECT  14.784 11.688 14.808 11.88 ;
    END
  END q[75]
  PIN q[76]
    DIRECTION OUTPUT ;
    USE SIGNAL ;
    PORT
      LAYER M5 ;
        RECT  14.976 11.688 15 11.88 ;
    END
  END q[76]
  PIN q[77]
    DIRECTION OUTPUT ;
    USE SIGNAL ;
    PORT
      LAYER M5 ;
        RECT  15.168 11.688 15.192 11.88 ;
    END
  END q[77]
  PIN q[78]
    DIRECTION OUTPUT ;
    USE SIGNAL ;
    PORT
      LAYER M5 ;
        RECT  15.36 11.688 15.384 11.88 ;
    END
  END q[78]
  PIN q[79]
    DIRECTION OUTPUT ;
    USE SIGNAL ;
    PORT
      LAYER M5 ;
        RECT  15.552 11.688 15.576 11.88 ;
    END
  END q[79]
  PIN q[7]
    DIRECTION OUTPUT ;
    USE SIGNAL ;
    PORT
      LAYER M5 ;
        RECT  1.728 11.688 1.752 11.88 ;
    END
  END q[7]
  PIN q[80]
    DIRECTION OUTPUT ;
    USE SIGNAL ;
    PORT
      LAYER M5 ;
        RECT  15.744 11.688 15.768 11.88 ;
    END
  END q[80]
  PIN q[81]
    DIRECTION OUTPUT ;
    USE SIGNAL ;
    PORT
      LAYER M5 ;
        RECT  15.936 11.688 15.96 11.88 ;
    END
  END q[81]
  PIN q[82]
    DIRECTION OUTPUT ;
    USE SIGNAL ;
    PORT
      LAYER M5 ;
        RECT  16.128 11.688 16.152 11.88 ;
    END
  END q[82]
  PIN q[83]
    DIRECTION OUTPUT ;
    USE SIGNAL ;
    PORT
      LAYER M5 ;
        RECT  16.32 11.688 16.344 11.88 ;
    END
  END q[83]
  PIN q[84]
    DIRECTION OUTPUT ;
    USE SIGNAL ;
    PORT
      LAYER M5 ;
        RECT  16.512 11.688 16.536 11.88 ;
    END
  END q[84]
  PIN q[85]
    DIRECTION OUTPUT ;
    USE SIGNAL ;
    PORT
      LAYER M5 ;
        RECT  16.704 11.688 16.728 11.88 ;
    END
  END q[85]
  PIN q[86]
    DIRECTION OUTPUT ;
    USE SIGNAL ;
    PORT
      LAYER M5 ;
        RECT  16.896 11.688 16.92 11.88 ;
    END
  END q[86]
  PIN q[87]
    DIRECTION OUTPUT ;
    USE SIGNAL ;
    PORT
      LAYER M5 ;
        RECT  17.088 11.688 17.112 11.88 ;
    END
  END q[87]
  PIN q[88]
    DIRECTION OUTPUT ;
    USE SIGNAL ;
    PORT
      LAYER M5 ;
        RECT  17.28 11.688 17.304 11.88 ;
    END
  END q[88]
  PIN q[89]
    DIRECTION OUTPUT ;
    USE SIGNAL ;
    PORT
      LAYER M5 ;
        RECT  17.472 11.688 17.496 11.88 ;
    END
  END q[89]
  PIN q[8]
    DIRECTION OUTPUT ;
    USE SIGNAL ;
    PORT
      LAYER M5 ;
        RECT  1.92 11.688 1.944 11.88 ;
    END
  END q[8]
  PIN q[90]
    DIRECTION OUTPUT ;
    USE SIGNAL ;
    PORT
      LAYER M5 ;
        RECT  17.664 11.688 17.688 11.88 ;
    END
  END q[90]
  PIN q[91]
    DIRECTION OUTPUT ;
    USE SIGNAL ;
    PORT
      LAYER M5 ;
        RECT  17.856 11.688 17.88 11.88 ;
    END
  END q[91]
  PIN q[92]
    DIRECTION OUTPUT ;
    USE SIGNAL ;
    PORT
      LAYER M5 ;
        RECT  18.048 11.688 18.072 11.88 ;
    END
  END q[92]
  PIN q[93]
    DIRECTION OUTPUT ;
    USE SIGNAL ;
    PORT
      LAYER M5 ;
        RECT  18.24 11.688 18.264 11.88 ;
    END
  END q[93]
  PIN q[94]
    DIRECTION OUTPUT ;
    USE SIGNAL ;
    PORT
      LAYER M5 ;
        RECT  18.432 11.688 18.456 11.88 ;
    END
  END q[94]
  PIN q[95]
    DIRECTION OUTPUT ;
    USE SIGNAL ;
    PORT
      LAYER M5 ;
        RECT  18.624 11.688 18.648 11.88 ;
    END
  END q[95]
  PIN q[96]
    DIRECTION OUTPUT ;
    USE SIGNAL ;
    PORT
      LAYER M5 ;
        RECT  18.816 11.688 18.84 11.88 ;
    END
  END q[96]
  PIN q[97]
    DIRECTION OUTPUT ;
    USE SIGNAL ;
    PORT
      LAYER M5 ;
        RECT  19.008 11.688 19.032 11.88 ;
    END
  END q[97]
  PIN q[98]
    DIRECTION OUTPUT ;
    USE SIGNAL ;
    PORT
      LAYER M5 ;
        RECT  19.2 11.688 19.224 11.88 ;
    END
  END q[98]
  PIN q[99]
    DIRECTION OUTPUT ;
    USE SIGNAL ;
    PORT
      LAYER M5 ;
        RECT  19.392 11.688 19.416 11.88 ;
    END
  END q[99]
  PIN q[9]
    DIRECTION OUTPUT ;
    USE SIGNAL ;
    PORT
      LAYER M5 ;
        RECT  2.112 11.688 2.136 11.88 ;
    END
  END q[9]
  PIN VDD
    DIRECTION INOUT ;
    USE POWER ;
    PORT
      LAYER M6 ;
        RECT  28.048 5.94 28.08 6.228 ;
        RECT  0 5.94 0.032 6.228 ;
        RECT  0 5.94 28.08 6.228 ;
      LAYER M2 ;
        RECT  28.062 11.061 28.08 11.079 ;
        RECT  0 11.061 0.018 11.079 ;
        RECT  28.062 10.521 28.08 10.539 ;
        RECT  0 10.521 0.018 10.539 ;
        RECT  28.062 9.981 28.08 9.999 ;
        RECT  0 9.981 0.018 9.999 ;
        RECT  28.062 9.441 28.08 9.459 ;
        RECT  0 9.441 0.018 9.459 ;
        RECT  28.062 8.901 28.08 8.919 ;
        RECT  0 8.901 0.018 8.919 ;
        RECT  28.062 8.361 28.08 8.379 ;
        RECT  0 8.361 0.018 8.379 ;
        RECT  28.062 7.821 28.08 7.839 ;
        RECT  0 7.821 0.018 7.839 ;
        RECT  28.062 7.281 28.08 7.299 ;
        RECT  0 7.281 0.018 7.299 ;
        RECT  28.062 6.741 28.08 6.759 ;
        RECT  0 6.741 0.018 6.759 ;
        RECT  28.062 6.201 28.08 6.219 ;
        RECT  0 6.201 0.018 6.219 ;
        RECT  28.062 5.661 28.08 5.679 ;
        RECT  0 5.661 0.018 5.679 ;
        RECT  28.062 5.121 28.08 5.139 ;
        RECT  0 5.121 0.018 5.139 ;
        RECT  28.062 4.581 28.08 4.599 ;
        RECT  0 4.581 0.018 4.599 ;
        RECT  28.062 4.041 28.08 4.059 ;
        RECT  0 4.041 0.018 4.059 ;
        RECT  28.062 3.501 28.08 3.519 ;
        RECT  0 3.501 0.018 3.519 ;
        RECT  28.062 2.961 28.08 2.979 ;
        RECT  0 2.961 0.018 2.979 ;
        RECT  28.062 2.421 28.08 2.439 ;
        RECT  0 2.421 0.018 2.439 ;
        RECT  28.062 1.881 28.08 1.899 ;
        RECT  0 1.881 0.018 1.899 ;
        RECT  28.062 1.341 28.08 1.359 ;
        RECT  0 1.341 0.018 1.359 ;
        RECT  28.062 0.801 28.08 0.819 ;
        RECT  0 0.801 0.018 0.819 ;
      LAYER M1 ;
        RECT  28.062 11.061 28.08 11.079 ;
        RECT  0 11.061 0.018 11.079 ;
        RECT  28.062 10.521 28.08 10.539 ;
        RECT  0 10.521 0.018 10.539 ;
        RECT  28.062 9.981 28.08 9.999 ;
        RECT  0 9.981 0.018 9.999 ;
        RECT  28.062 9.441 28.08 9.459 ;
        RECT  0 9.441 0.018 9.459 ;
        RECT  28.062 8.901 28.08 8.919 ;
        RECT  0 8.901 0.018 8.919 ;
        RECT  28.062 8.361 28.08 8.379 ;
        RECT  0 8.361 0.018 8.379 ;
        RECT  28.062 7.821 28.08 7.839 ;
        RECT  0 7.821 0.018 7.839 ;
        RECT  28.062 7.281 28.08 7.299 ;
        RECT  0 7.281 0.018 7.299 ;
        RECT  28.062 6.741 28.08 6.759 ;
        RECT  0 6.741 0.018 6.759 ;
        RECT  28.062 6.201 28.08 6.219 ;
        RECT  0 6.201 0.018 6.219 ;
        RECT  28.062 5.661 28.08 5.679 ;
        RECT  0 5.661 0.018 5.679 ;
        RECT  28.062 5.121 28.08 5.139 ;
        RECT  0 5.121 0.018 5.139 ;
        RECT  28.062 4.581 28.08 4.599 ;
        RECT  0 4.581 0.018 4.599 ;
        RECT  28.062 4.041 28.08 4.059 ;
        RECT  0 4.041 0.018 4.059 ;
        RECT  28.062 3.501 28.08 3.519 ;
        RECT  0 3.501 0.018 3.519 ;
        RECT  28.062 2.961 28.08 2.979 ;
        RECT  0 2.961 0.018 2.979 ;
        RECT  28.062 2.421 28.08 2.439 ;
        RECT  0 2.421 0.018 2.439 ;
        RECT  28.062 1.881 28.08 1.899 ;
        RECT  0 1.881 0.018 1.899 ;
        RECT  28.062 1.341 28.08 1.359 ;
        RECT  0 1.341 0.018 1.359 ;
        RECT  28.062 0.801 28.08 0.819 ;
        RECT  0 0.801 0.018 0.819 ;
    END
  END VDD
  PIN VSS
    DIRECTION INOUT ;
    USE GROUND ;
    PORT
      LAYER M6 ;
        RECT  28.048 5.364 28.08 5.652 ;
        RECT  0 5.364 0.032 5.652 ;
        RECT  0 5.364 28.08 5.652 ;
      LAYER M2 ;
        RECT  28.062 11.331 28.08 11.349 ;
        RECT  0 11.331 0.018 11.349 ;
        RECT  28.062 10.791 28.08 10.809 ;
        RECT  0 10.791 0.018 10.809 ;
        RECT  28.062 10.251 28.08 10.269 ;
        RECT  0 10.251 0.018 10.269 ;
        RECT  28.062 9.711 28.08 9.729 ;
        RECT  0 9.711 0.018 9.729 ;
        RECT  28.062 9.171 28.08 9.189 ;
        RECT  0 9.171 0.018 9.189 ;
        RECT  28.062 8.631 28.08 8.649 ;
        RECT  0 8.631 0.018 8.649 ;
        RECT  28.062 8.091 28.08 8.109 ;
        RECT  0 8.091 0.018 8.109 ;
        RECT  28.062 7.551 28.08 7.569 ;
        RECT  0 7.551 0.018 7.569 ;
        RECT  28.062 7.011 28.08 7.029 ;
        RECT  0 7.011 0.018 7.029 ;
        RECT  28.062 6.471 28.08 6.489 ;
        RECT  0 6.471 0.018 6.489 ;
        RECT  28.062 5.931 28.08 5.949 ;
        RECT  0 5.931 0.018 5.949 ;
        RECT  28.062 5.391 28.08 5.409 ;
        RECT  0 5.391 0.018 5.409 ;
        RECT  28.062 4.851 28.08 4.869 ;
        RECT  0 4.851 0.018 4.869 ;
        RECT  28.062 4.311 28.08 4.329 ;
        RECT  0 4.311 0.018 4.329 ;
        RECT  28.062 3.771 28.08 3.789 ;
        RECT  0 3.771 0.018 3.789 ;
        RECT  28.062 3.231 28.08 3.249 ;
        RECT  0 3.231 0.018 3.249 ;
        RECT  28.062 2.691 28.08 2.709 ;
        RECT  0 2.691 0.018 2.709 ;
        RECT  28.062 2.151 28.08 2.169 ;
        RECT  0 2.151 0.018 2.169 ;
        RECT  28.062 1.611 28.08 1.629 ;
        RECT  0 1.611 0.018 1.629 ;
        RECT  28.062 1.071 28.08 1.089 ;
        RECT  0 1.071 0.018 1.089 ;
        RECT  28.062 0.531 28.08 0.549 ;
        RECT  0 0.531 0.018 0.549 ;
      LAYER M1 ;
        RECT  28.062 11.331 28.08 11.349 ;
        RECT  0 11.331 0.018 11.349 ;
        RECT  28.062 10.791 28.08 10.809 ;
        RECT  0 10.791 0.018 10.809 ;
        RECT  28.062 10.251 28.08 10.269 ;
        RECT  0 10.251 0.018 10.269 ;
        RECT  28.062 9.711 28.08 9.729 ;
        RECT  0 9.711 0.018 9.729 ;
        RECT  28.062 9.171 28.08 9.189 ;
        RECT  0 9.171 0.018 9.189 ;
        RECT  28.062 8.631 28.08 8.649 ;
        RECT  0 8.631 0.018 8.649 ;
        RECT  28.062 8.091 28.08 8.109 ;
        RECT  0 8.091 0.018 8.109 ;
        RECT  28.062 7.551 28.08 7.569 ;
        RECT  0 7.551 0.018 7.569 ;
        RECT  28.062 7.011 28.08 7.029 ;
        RECT  0 7.011 0.018 7.029 ;
        RECT  28.062 6.471 28.08 6.489 ;
        RECT  0 6.471 0.018 6.489 ;
        RECT  28.062 5.931 28.08 5.949 ;
        RECT  0 5.931 0.018 5.949 ;
        RECT  28.062 5.391 28.08 5.409 ;
        RECT  0 5.391 0.018 5.409 ;
        RECT  28.062 4.851 28.08 4.869 ;
        RECT  0 4.851 0.018 4.869 ;
        RECT  28.062 4.311 28.08 4.329 ;
        RECT  0 4.311 0.018 4.329 ;
        RECT  28.062 3.771 28.08 3.789 ;
        RECT  0 3.771 0.018 3.789 ;
        RECT  28.062 3.231 28.08 3.249 ;
        RECT  0 3.231 0.018 3.249 ;
        RECT  28.062 2.691 28.08 2.709 ;
        RECT  0 2.691 0.018 2.709 ;
        RECT  28.062 2.151 28.08 2.169 ;
        RECT  0 2.151 0.018 2.169 ;
        RECT  28.062 1.611 28.08 1.629 ;
        RECT  0 1.611 0.018 1.629 ;
        RECT  28.062 1.071 28.08 1.089 ;
        RECT  0 1.071 0.018 1.089 ;
        RECT  28.062 0.531 28.08 0.549 ;
        RECT  0 0.531 0.018 0.549 ;
    END
  END VSS
  OBS
    LAYER RVTN ;
     RECT  0 0.54 28.08 0.675 ;
     RECT  0 0.945 28.08 1.215 ;
     RECT  0 1.485 28.08 1.755 ;
     RECT  0 2.025 28.08 2.295 ;
     RECT  0 2.565 28.08 2.835 ;
     RECT  0 3.105 28.08 3.375 ;
     RECT  0 3.645 28.08 3.915 ;
     RECT  0 4.185 28.08 4.455 ;
     RECT  0 4.725 28.08 4.995 ;
     RECT  0 5.265 28.08 5.535 ;
     RECT  0 5.805 28.08 6.075 ;
     RECT  0 6.345 28.08 6.615 ;
     RECT  0 6.885 28.08 7.155 ;
     RECT  0 7.425 28.08 7.695 ;
     RECT  0 7.965 28.08 8.235 ;
     RECT  0 8.505 28.08 8.775 ;
     RECT  0 9.045 28.08 9.315 ;
     RECT  0 9.585 28.08 9.855 ;
     RECT  0 10.125 28.08 10.395 ;
     RECT  0 10.665 28.08 10.935 ;
     RECT  0 11.205 28.08 11.34 ;
    LAYER RVTP ;
     RECT  0 0.675 28.08 0.945 ;
     RECT  0 1.215 28.08 1.485 ;
     RECT  0 1.755 28.08 2.025 ;
     RECT  0 2.295 28.08 2.565 ;
     RECT  0 2.835 28.08 3.105 ;
     RECT  0 3.375 28.08 3.645 ;
     RECT  0 3.915 28.08 4.185 ;
     RECT  0 4.455 28.08 4.725 ;
     RECT  0 4.995 28.08 5.265 ;
     RECT  0 5.535 28.08 5.805 ;
     RECT  0 6.075 28.08 6.345 ;
     RECT  0 6.615 28.08 6.885 ;
     RECT  0 7.155 28.08 7.425 ;
     RECT  0 7.695 28.08 7.965 ;
     RECT  0 8.235 28.08 8.505 ;
     RECT  0 8.775 28.08 9.045 ;
     RECT  0 9.315 28.08 9.585 ;
     RECT  0 9.855 28.08 10.125 ;
     RECT  0 10.395 28.08 10.665 ;
     RECT  0 10.935 28.08 11.205 ;
    LAYER M1 ;
     RECT  0 0.531 28.08 11.349 ;
    LAYER M2 ;
     RECT  0 0.531 28.08 11.349 ;
    LAYER M3 ;
     RECT  15.912 0.187 15.93 0.235 ;
     RECT  17.1 0.187 17.118 0.235 ;
     RECT  0.468 0.379 0.486 0.523 ;
     RECT  11.196 0.379 11.214 0.523 ;
     RECT  22.5 0.187 25.11 0.523 ;
     RECT  0.255 0.523 0.486 0.571 ;
     RECT  1.584 0.187 1.602 0.571 ;
     RECT  3.06 0.187 3.078 0.571 ;
     RECT  3.996 0.187 4.266 0.571 ;
     RECT  5.04 0.187 5.814 0.571 ;
     RECT  7.38 0.187 8.406 0.571 ;
     RECT  11.055 0.523 11.214 0.571 ;
     RECT  12.24 0.187 13.806 0.571 ;
     RECT  15.912 0.235 17.118 0.571 ;
     RECT  18.288 0.187 18.846 0.571 ;
     RECT  20.988 0.187 21.006 0.571 ;
     RECT  21.855 0.523 25.11 0.571 ;
     RECT  26.172 0.187 26.334 0.571 ;
     RECT  0.255 0.571 26.334 0.751 ;
     RECT  27.255 0.523 27.345 0.793 ;
     RECT  0.255 0.751 26.37 1.021 ;
     RECT  27.255 0.793 27.537 1.021 ;
     RECT  0.255 1.021 27.537 1.255 ;
     RECT  0.216 1.255 27.537 1.445 ;
     RECT  0.216 1.445 26.298 2.129 ;
     RECT  0.255 2.129 26.298 2.371 ;
     RECT  0.255 2.371 26.478 2.489 ;
     RECT  0.255 2.489 26.334 3.307 ;
     RECT  27.255 1.445 27.537 3.307 ;
     RECT  0.255 3.307 27.537 5.117 ;
     RECT  0.255 5.117 14.742 5.459 ;
     RECT  15.804 5.117 27.537 5.459 ;
     RECT  0.255 5.459 14.67 5.467 ;
     RECT  0.252 5.467 14.67 5.501 ;
     RECT  0.255 5.501 14.67 5.693 ;
     RECT  12.924 5.693 14.67 5.837 ;
     RECT  15.804 5.459 19.746 5.881 ;
     RECT  12.924 5.837 14.634 5.999 ;
     RECT  15.444 5.881 19.746 6.235 ;
     RECT  20.484 5.459 27.537 6.235 ;
     RECT  12.993 5.999 14.634 6.267 ;
     RECT  0.255 5.693 12.15 6.269 ;
     RECT  12.996 6.267 14.634 6.269 ;
     RECT  0.255 6.269 9.702 6.317 ;
     RECT  13.032 6.269 14.634 6.691 ;
     RECT  15.444 6.235 27.537 6.691 ;
     RECT  13.032 6.691 27.537 6.845 ;
     RECT  10.512 6.269 12.15 7.231 ;
     RECT  13.032 6.845 14.814 7.231 ;
     RECT  0.255 6.317 8.334 7.321 ;
     RECT  9.108 6.317 9.702 7.321 ;
     RECT  15.588 6.845 27.537 7.421 ;
     RECT  0.255 7.321 9.702 7.501 ;
     RECT  10.512 7.231 14.814 7.501 ;
     RECT  15.588 7.421 22.986 7.691 ;
     RECT  0.255 7.501 14.814 7.735 ;
     RECT  0.252 7.735 14.814 7.771 ;
     RECT  15.588 7.691 22.95 7.771 ;
     RECT  0.252 7.771 22.95 7.889 ;
     RECT  0.255 7.889 22.95 8.771 ;
     RECT  13.032 8.771 22.95 8.851 ;
     RECT  23.904 7.421 27.537 8.851 ;
     RECT  0.255 8.771 12.15 9.149 ;
     RECT  13.032 8.851 27.537 9.245 ;
     RECT  13.212 9.245 27.537 9.677 ;
     RECT  10.764 9.149 12.15 9.691 ;
     RECT  13.212 9.677 14.634 10.085 ;
     RECT  0.255 9.149 8.226 10.201 ;
     RECT  9.108 9.149 9.882 10.201 ;
     RECT  10.764 9.691 12.186 10.201 ;
     RECT  15.516 9.677 27.537 10.253 ;
     RECT  0.255 10.201 13.086 10.301 ;
     RECT  13.932 10.085 14.634 10.319 ;
     RECT  14.076 10.319 14.634 10.349 ;
     RECT  14.112 10.349 14.634 10.471 ;
     RECT  15.516 10.253 17.37 10.471 ;
     RECT  14.112 10.471 17.37 10.541 ;
     RECT  0.255 10.301 12.726 10.829 ;
     RECT  2.916 10.829 12.726 10.877 ;
     RECT  15.66 10.541 17.37 10.877 ;
     RECT  18.18 10.253 27.537 10.877 ;
     RECT  18.18 10.877 26.082 10.925 ;
     RECT  12.456 10.877 12.726 11.069 ;
     RECT  18.18 10.925 25.398 11.069 ;
     RECT  16.02 10.877 16.737 11.087 ;
     RECT  27.255 10.877 27.537 11.087 ;
     RECT  5.328 10.877 7.146 11.165 ;
     RECT  8.208 10.877 11.682 11.165 ;
     RECT  12.708 11.069 12.726 11.165 ;
     RECT  14.112 10.541 14.922 11.165 ;
     RECT  16.02 11.087 16.545 11.165 ;
     RECT  23.112 11.069 25.398 11.165 ;
     RECT  2.916 10.877 4.23 11.201 ;
     RECT  14.256 11.165 14.922 11.201 ;
     RECT  8.316 11.165 11.682 11.273 ;
     RECT  18.18 11.069 22.374 11.273 ;
     RECT  0.255 10.829 1.746 11.357 ;
     RECT  2.916 11.201 3.906 11.357 ;
     RECT  5.436 11.165 6.282 11.357 ;
     RECT  7.128 11.165 7.146 11.357 ;
     RECT  8.316 11.273 8.91 11.357 ;
     RECT  9.792 11.273 11.682 11.357 ;
     RECT  12.78 11.281 12.798 11.357 ;
     RECT  14.256 11.201 14.85 11.357 ;
     RECT  16.128 11.165 16.545 11.357 ;
     RECT  17.748 11.281 17.766 11.357 ;
     RECT  18.9 11.273 22.374 11.357 ;
     RECT  23.112 11.165 24.606 11.357 ;
     RECT  25.38 11.165 25.398 11.357 ;
     RECT  27.255 11.087 27.345 11.357 ;
     RECT  0.468 11.357 1.134 11.405 ;
     RECT  24.012 11.357 24.03 11.405 ;
     RECT  0.468 11.405 0.486 11.501 ;
     RECT  5.796 11.357 6.282 11.501 ;
     RECT  22.032 11.357 22.05 11.501 ;
     RECT  5.796 11.501 5.814 11.549 ;
     RECT  10.008 11.357 10.026 11.789 ;
    LAYER M4 ;
     RECT  0.133 5.928 0.241 6.024 ;
     RECT  0.241 5.472 0.248 6.024 ;
     RECT  0.248 0.528 0.373 11.352 ;
     RECT  0.373 0.384 0.497 11.496 ;
     RECT  0.497 0.576 0.544 11.4 ;
     RECT  0.544 8.496 0.755 9.144 ;
     RECT  0.544 3.936 1.145 3.96 ;
     RECT  0.544 11.328 1.145 11.4 ;
     RECT  0.544 10.224 1.397 10.344 ;
     RECT  0.544 0.576 1.525 1.176 ;
     RECT  1.397 10.272 1.525 10.344 ;
     RECT  1.145 11.328 1.525 11.352 ;
     RECT  1.525 0.192 1.613 1.176 ;
     RECT  0.544 2.784 1.715 2.808 ;
     RECT  1.861 3.504 1.907 3.528 ;
     RECT  0.755 9.12 1.909 9.144 ;
     RECT  1.909 9.12 2.485 9.24 ;
     RECT  1.525 10.272 2.485 11.352 ;
     RECT  0.544 5.472 2.579 6.024 ;
     RECT  1.613 0.576 2.761 1.176 ;
     RECT  0.544 7.392 2.761 7.416 ;
     RECT  2.761 7.056 2.801 7.416 ;
     RECT  2.761 0.576 2.819 1.752 ;
     RECT  2.819 0.576 3.049 1.176 ;
     RECT  2.485 9.12 3.449 11.352 ;
     RECT  3.449 10.176 3.557 11.352 ;
     RECT  2.533 4.272 3.661 4.296 ;
     RECT  3.661 4.272 3.701 4.536 ;
     RECT  3.265 2.784 3.733 2.808 ;
     RECT  2.579 6 3.781 6.024 ;
     RECT  2.801 7.056 3.781 7.08 ;
     RECT  3.049 0.192 3.875 1.176 ;
     RECT  3.733 2.784 3.875 2.952 ;
     RECT  3.449 9.12 3.913 9.144 ;
     RECT  3.557 10.272 3.917 11.352 ;
     RECT  3.973 1.68 4.025 1.704 ;
     RECT  3.701 4.512 4.129 4.536 ;
     RECT  3.781 6 4.129 7.08 ;
     RECT  3.913 8.592 4.213 9.144 ;
     RECT  4.129 4.512 4.313 7.08 ;
     RECT  3.875 2.784 4.405 2.808 ;
     RECT  4.405 2.352 4.493 2.808 ;
     RECT  3.917 10.272 4.597 10.872 ;
     RECT  4.313 4.512 4.601 6.888 ;
     RECT  4.213 8.544 4.669 9.144 ;
     RECT  4.669 7.872 4.981 9.144 ;
     RECT  4.981 7.872 5.077 9.192 ;
     RECT  4.597 10.224 5.077 10.872 ;
     RECT  5.077 7.872 5.365 10.872 ;
     RECT  4.885 2.88 5.509 2.904 ;
     RECT  5.365 7.872 5.557 11.352 ;
     RECT  3.875 0.192 5.648 0.6 ;
     RECT  5.509 2.352 5.648 2.904 ;
     RECT  4.669 4.464 5.648 4.488 ;
     RECT  4.601 5.616 5.648 6.888 ;
     RECT  5.557 7.872 5.648 11.496 ;
     RECT  5.648 0.192 5.749 11.496 ;
     RECT  5.749 0.192 5.825 11.544 ;
     RECT  5.825 0.576 5.944 11.496 ;
     RECT  5.944 2.208 6.083 2.328 ;
     RECT  5.944 5.664 6.083 6.888 ;
     RECT  5.944 10.8 6.293 11.496 ;
     RECT  5.944 7.872 6.545 7.896 ;
     RECT  5.944 9.12 6.545 9.72 ;
     RECT  6.545 9.12 6.833 9.144 ;
     RECT  6.083 2.304 6.977 2.328 ;
     RECT  6.293 10.8 7.093 11.352 ;
     RECT  5.944 0.576 7.153 1.176 ;
     RECT  7.153 0.576 7.285 1.56 ;
     RECT  7.261 2.64 7.405 2.952 ;
     RECT  5.944 4.368 7.405 4.536 ;
     RECT  7.285 0.192 7.553 1.56 ;
     RECT  6.083 5.664 7.585 6.024 ;
     RECT  7.405 7.392 7.585 7.416 ;
     RECT  7.093 10.224 7.669 11.352 ;
     RECT  7.405 2.64 7.909 4.536 ;
     RECT  7.585 5.664 7.909 7.416 ;
     RECT  7.909 2.64 7.955 7.416 ;
     RECT  7.955 2.64 7.957 6.264 ;
     RECT  7.669 9.648 7.985 11.352 ;
     RECT  7.957 2.208 8.129 6.264 ;
     RECT  7.955 7.392 8.233 7.416 ;
     RECT  8.233 7.392 8.273 7.944 ;
     RECT  8.273 7.44 8.435 7.944 ;
     RECT  7.553 0.192 8.483 0.6 ;
     RECT  8.129 2.4 8.531 6.264 ;
     RECT  8.435 7.92 8.557 7.944 ;
     RECT  8.377 9.072 8.557 9.144 ;
     RECT  8.531 3.744 8.597 4.872 ;
     RECT  8.531 2.4 8.669 2.76 ;
     RECT  8.483 0.576 8.701 0.6 ;
     RECT  8.597 4.368 8.777 4.872 ;
     RECT  8.669 2.4 8.957 2.664 ;
     RECT  8.531 6 8.989 6.264 ;
     RECT  8.557 7.92 9.013 9.144 ;
     RECT  7.985 10.224 9.013 11.352 ;
     RECT  8.989 6 9.107 6.312 ;
     RECT  9.107 6 9.245 6.264 ;
     RECT  8.957 2.4 9.317 2.424 ;
     RECT  9.013 7.92 9.389 11.352 ;
     RECT  9.389 8.16 9.971 11.352 ;
     RECT  9.971 8.496 9.973 11.352 ;
     RECT  8.777 4.368 9.997 4.68 ;
     RECT  9.245 6 9.997 6.12 ;
     RECT  9.973 8.496 9.997 11.688 ;
     RECT  9.997 8.496 10.067 11.784 ;
     RECT  10.117 3.312 10.213 3.336 ;
     RECT  9.997 4.368 10.213 6.12 ;
     RECT  10.067 8.496 10.933 11.496 ;
     RECT  8.701 0.576 11.048 1.176 ;
     RECT  10.213 3.312 11.048 6.264 ;
     RECT  10.933 7.968 11.048 11.496 ;
     RECT  11.048 0.528 11.125 11.496 ;
     RECT  11.125 0.384 11.171 11.496 ;
     RECT  11.171 0.384 11.225 11.352 ;
     RECT  11.225 0.576 11.344 11.352 ;
     RECT  11.344 5.568 11.987 6.888 ;
     RECT  11.987 5.568 12.125 6.216 ;
     RECT  11.344 0.576 12.229 1.176 ;
     RECT  11.344 2.928 12.445 4.536 ;
     RECT  12.125 5.568 12.445 6.117 ;
     RECT  11.344 9.12 12.485 11.352 ;
     RECT  12.445 2.928 12.515 6.117 ;
     RECT  12.485 9.12 12.515 10.296 ;
     RECT  12.515 3.408 12.563 6.117 ;
     RECT  12.229 0.192 12.737 1.176 ;
     RECT  12.485 11.328 12.809 11.352 ;
     RECT  12.563 3.408 12.845 4.536 ;
     RECT  12.845 3.744 13.385 4.536 ;
     RECT  12.563 5.664 13.525 6.117 ;
     RECT  13.381 7.392 13.525 7.416 ;
     RECT  12.515 10.272 13.525 10.296 ;
     RECT  12.515 9.12 13.621 9.24 ;
     RECT  13.525 10.272 13.621 10.392 ;
     RECT  13.525 5.664 13.667 7.416 ;
     RECT  13.621 8.4 13.673 10.392 ;
     RECT  12.737 0.192 13.859 0.6 ;
     RECT  13.673 8.4 13.957 9.144 ;
     RECT  13.673 10.224 14.005 10.392 ;
     RECT  13.957 7.968 14.099 9.144 ;
     RECT  13.667 5.664 14.101 6.261 ;
     RECT  13.385 4.128 14.173 4.536 ;
     RECT  14.101 5.568 14.173 6.261 ;
     RECT  13.859 0.576 14.197 0.6 ;
     RECT  14.005 10.224 14.197 10.872 ;
     RECT  14.197 0.576 14.249 1.176 ;
     RECT  14.173 4.128 14.723 6.261 ;
     RECT  14.197 10.224 14.773 11.352 ;
     RECT  14.749 2.304 14.821 2.328 ;
     RECT  14.773 9.648 14.861 11.352 ;
     RECT  14.723 4.128 14.869 5.112 ;
     RECT  14.869 3.744 15.113 5.112 ;
     RECT  14.821 2.256 15.145 2.328 ;
     RECT  15.113 3.744 15.145 4.728 ;
     RECT  14.099 7.968 15.349 8.184 ;
     RECT  14.861 9.648 15.349 10.872 ;
     RECT  14.249 0.576 15.397 0.6 ;
     RECT  15.145 2.256 15.401 4.728 ;
     RECT  15.349 7.968 15.401 10.872 ;
     RECT  14.723 6.243 15.433 6.261 ;
     RECT  15.433 6.243 15.577 6.84 ;
     RECT  15.401 7.968 15.577 8.184 ;
     RECT  15.397 0.576 15.757 0.792 ;
     RECT  15.577 6.243 15.829 8.184 ;
     RECT  15.757 0.576 15.901 1.704 ;
     RECT  15.901 0.192 15.971 1.704 ;
     RECT  15.401 9.504 16.117 10.872 ;
     RECT  15.401 2.688 16.165 4.728 ;
     RECT  15.829 6.096 16.165 8.184 ;
     RECT  16.117 9.504 16.261 11.352 ;
     RECT  15.971 0.24 16.448 1.704 ;
     RECT  16.165 2.688 16.448 8.184 ;
     RECT  16.261 9.504 16.448 11.496 ;
     RECT  16.448 0.24 16.547 11.496 ;
     RECT  16.547 0.24 16.552 11.352 ;
     RECT  16.552 0.24 16.744 11.208 ;
     RECT  16.744 0.24 16.883 6.84 ;
     RECT  16.744 8.16 16.883 11.208 ;
     RECT  16.883 0.24 17.027 6.792 ;
     RECT  17.027 0.24 17.077 1.8 ;
     RECT  17.077 0.192 17.129 1.8 ;
     RECT  17.027 2.832 17.381 5.928 ;
     RECT  17.381 2.976 17.489 5.928 ;
     RECT  16.883 8.403 17.507 9.72 ;
     RECT  17.489 3.312 17.597 5.928 ;
     RECT  17.129 0.576 17.603 1.8 ;
     RECT  17.597 5.136 17.651 5.928 ;
     RECT  16.883 10.848 17.653 11.208 ;
     RECT  17.597 3.312 17.669 4.104 ;
     RECT  17.507 9.408 17.669 9.72 ;
     RECT  17.651 5.904 17.741 5.928 ;
     RECT  17.653 10.848 17.777 11.352 ;
     RECT  17.669 9.696 17.845 9.72 ;
     RECT  17.777 10.848 17.845 10.92 ;
     RECT  17.669 3.312 17.885 3.336 ;
     RECT  17.603 0.576 18.229 1.704 ;
     RECT  17.507 8.403 18.421 8.421 ;
     RECT  18.229 0.192 18.569 1.704 ;
     RECT  17.845 9.696 18.659 10.92 ;
     RECT  18.659 10.224 18.677 10.92 ;
     RECT  18.677 10.272 18.805 10.92 ;
     RECT  18.569 0.192 18.857 1.176 ;
     RECT  18.613 5.616 18.889 5.64 ;
     RECT  18.805 2.928 19.189 2.952 ;
     RECT  18.421 8.016 19.189 8.421 ;
     RECT  18.857 0.576 19.235 1.176 ;
     RECT  19.189 8.016 19.361 9.144 ;
     RECT  19.189 2.928 19.465 3.768 ;
     RECT  18.889 5.616 19.469 6.264 ;
     RECT  19.361 8.016 19.501 8.568 ;
     RECT  19.465 2.928 19.573 3.864 ;
     RECT  19.573 2.304 19.649 3.864 ;
     RECT  19.681 5.136 19.825 5.16 ;
     RECT  19.649 2.928 19.907 3.864 ;
     RECT  19.501 7.968 19.969 8.568 ;
     RECT  19.969 7.584 20.113 8.568 ;
     RECT  19.469 6.24 20.197 6.264 ;
     RECT  20.113 7.44 20.197 8.568 ;
     RECT  19.907 3.84 20.245 3.864 ;
     RECT  19.825 5.088 20.245 5.16 ;
     RECT  20.197 6.24 20.291 8.568 ;
     RECT  20.245 3.84 20.333 5.16 ;
     RECT  19.235 0.576 20.533 1.08 ;
     RECT  20.291 7.872 20.533 8.568 ;
     RECT  20.533 0.576 20.585 1.176 ;
     RECT  20.333 5.136 20.677 5.16 ;
     RECT  20.291 6.24 20.677 6.84 ;
     RECT  20.677 5.136 20.723 6.84 ;
     RECT  20.723 5.52 20.765 6.84 ;
     RECT  20.725 2.304 20.801 2.328 ;
     RECT  20.585 0.576 20.917 0.6 ;
     RECT  20.917 0.192 21.017 0.6 ;
     RECT  18.805 10.272 21.301 11.352 ;
     RECT  20.333 3.84 21.349 3.96 ;
     RECT  21.349 3.84 21.625 4.536 ;
     RECT  21.017 0.288 21.637 0.6 ;
     RECT  21.625 2.928 21.733 4.536 ;
     RECT  20.765 5.52 21.733 5.544 ;
     RECT  21.637 0.288 21.848 0.696 ;
     RECT  21.733 1.68 21.848 1.704 ;
     RECT  21.733 2.928 21.848 5.544 ;
     RECT  20.765 6.816 21.848 6.84 ;
     RECT  20.533 7.872 21.848 9.096 ;
     RECT  21.301 10.224 21.848 11.352 ;
     RECT  21.848 0.288 21.877 11.352 ;
     RECT  21.877 0.288 22.061 11.496 ;
     RECT  22.061 0.288 22.144 11.352 ;
     RECT  22.144 0.288 22.453 0.6 ;
     RECT  22.144 9.696 22.601 11.352 ;
     RECT  22.144 2.304 22.787 3.864 ;
     RECT  22.144 5.424 23.221 5.928 ;
     RECT  22.144 8.256 23.363 8.568 ;
     RECT  22.453 0.192 23.365 0.6 ;
     RECT  23.365 0.192 23.461 0.888 ;
     RECT  23.363 8.256 23.461 8.28 ;
     RECT  23.221 4.992 23.501 5.928 ;
     RECT  23.461 7.392 23.507 8.28 ;
     RECT  23.501 5.472 23.557 5.928 ;
     RECT  23.507 7.392 23.557 7.416 ;
     RECT  22.787 2.304 23.569 3.528 ;
     RECT  23.557 5.472 23.603 7.416 ;
     RECT  22.601 11.328 23.605 11.352 ;
     RECT  23.569 2.256 23.701 3.528 ;
     RECT  22.601 9.696 23.747 10.344 ;
     RECT  23.747 10.032 23.797 10.344 ;
     RECT  23.605 11.328 23.797 11.4 ;
     RECT  23.701 2.208 23.845 3.528 ;
     RECT  23.603 5.472 23.891 6.888 ;
     RECT  23.461 0.192 23.941 1.176 ;
     RECT  23.845 2.208 23.941 4.296 ;
     RECT  23.941 0.192 23.969 4.296 ;
     RECT  23.969 0.192 24.005 4.104 ;
     RECT  24.005 3.504 24.041 4.104 ;
     RECT  23.797 10.032 24.041 11.4 ;
     RECT  24.041 3.504 24.725 3.528 ;
     RECT  24.041 10.032 24.757 11.352 ;
     RECT  24.757 8.544 25.043 8.568 ;
     RECT  24.757 9.696 25.091 11.352 ;
     RECT  24.005 0.192 25.121 2.28 ;
     RECT  23.891 5.472 25.157 6.696 ;
     RECT  25.121 0.576 25.225 2.28 ;
     RECT  25.091 10.128 25.229 11.352 ;
     RECT  25.157 5.472 25.265 6.408 ;
     RECT  25.225 0.576 25.283 2.376 ;
     RECT  25.229 10.848 25.409 11.352 ;
     RECT  25.265 6.384 25.475 6.408 ;
     RECT  25.477 3.84 25.553 3.864 ;
     RECT  25.525 9.12 25.661 9.144 ;
     RECT  25.283 0.576 25.697 2.328 ;
     RECT  25.697 2.304 25.733 2.328 ;
     RECT  25.697 0.576 25.955 1.176 ;
     RECT  25.409 10.848 26.093 10.92 ;
     RECT  26.101 0.192 26.345 0.216 ;
     RECT  26.101 5.088 27.248 5.112 ;
     RECT  26.093 10.848 27.248 10.872 ;
     RECT  27.248 0.528 27.352 11.352 ;
     RECT  27.352 0.798 27.544 11.082 ;
    LAYER M5 ;
     RECT  0.384 0.144 26.328 0.227 ;
     RECT  0.384 0.227 25.944 0.517 ;
     RECT  0.24 0.517 25.944 0.611 ;
     RECT  15.408 0.611 22.152 0.747 ;
     RECT  27.24 0.517 27.36 0.787 ;
     RECT  15.408 0.747 20.76 0.811 ;
     RECT  23.376 0.611 25.944 0.939 ;
     RECT  23.712 0.939 25.944 1.067 ;
     RECT  15.792 0.811 20.76 1.131 ;
     RECT  0.24 0.611 3.864 1.187 ;
     RECT  5.64 0.611 7.512 1.187 ;
     RECT  8.832 0.611 12.696 1.187 ;
     RECT  14.208 0.611 14.232 1.187 ;
     RECT  15.792 1.131 19.224 1.187 ;
     RECT  20.544 1.131 20.76 1.187 ;
     RECT  23.808 1.067 25.944 1.187 ;
     RECT  7.2 1.187 7.512 1.579 ;
     RECT  3.984 1.653 4.008 1.715 ;
     RECT  15.792 1.187 18.552 1.715 ;
     RECT  21.744 0.747 22.152 1.715 ;
     RECT  2.784 1.187 2.808 1.771 ;
     RECT  15.792 1.715 17.592 1.811 ;
     RECT  5.64 1.187 5.952 2.197 ;
     RECT  23.952 1.187 23.976 2.197 ;
     RECT  15.792 1.811 17.016 2.229 ;
     RECT  23.712 2.197 24.408 2.283 ;
     RECT  5.64 2.197 6.072 2.293 ;
     RECT  15.36 2.229 17.016 2.293 ;
     RECT  21.84 1.715 22.152 2.293 ;
     RECT  23.712 2.283 23.976 2.293 ;
     RECT  20.736 1.187 20.76 2.339 ;
     RECT  5.52 2.293 6.936 2.347 ;
     RECT  14.784 2.293 17.016 2.347 ;
     RECT  25.248 2.293 25.272 2.387 ;
     RECT  4.416 2.293 4.44 2.677 ;
     RECT  5.52 2.347 5.952 2.677 ;
     RECT  7.968 2.197 7.992 2.725 ;
     RECT  3.408 2.677 3.432 2.773 ;
     RECT  4.416 2.677 5.952 2.773 ;
     RECT  7.968 2.725 8.568 2.795 ;
     RECT  15.264 2.347 17.016 2.805 ;
     RECT  1.68 2.773 1.704 2.859 ;
     RECT  3.408 2.773 5.952 2.859 ;
     RECT  7.968 2.795 8.52 2.869 ;
     RECT  19.584 2.293 19.608 2.869 ;
     RECT  21.84 2.293 23.976 2.869 ;
     RECT  4.896 2.859 5.952 2.915 ;
     RECT  15.264 2.805 17.352 2.933 ;
     RECT  3.84 2.859 3.864 2.963 ;
     RECT  7.344 2.869 8.52 2.963 ;
     RECT  18.816 2.869 19.896 2.963 ;
     RECT  21.648 2.869 23.976 2.963 ;
     RECT  11.04 1.187 11.352 3.301 ;
     RECT  15.264 2.933 17.4 3.301 ;
     RECT  19.2 2.963 19.56 3.371 ;
     RECT  10.128 3.301 11.352 3.397 ;
     RECT  12.48 2.869 12.504 3.397 ;
     RECT  21.84 2.963 23.976 3.445 ;
     RECT  1.872 3.445 1.896 3.539 ;
     RECT  7.728 2.963 8.52 3.539 ;
     RECT  21.84 3.445 24.552 3.539 ;
     RECT  10.128 3.397 12.552 3.733 ;
     RECT  15.264 3.301 17.64 3.733 ;
     RECT  10.128 3.733 13.368 3.819 ;
     RECT  21.84 3.539 22.776 3.875 ;
     RECT  25.488 3.829 25.512 3.883 ;
     RECT  0.24 1.187 0.552 3.925 ;
     RECT  0.24 3.925 1.128 4.011 ;
     RECT  23.856 3.539 23.976 4.115 ;
     RECT  14.88 3.733 17.64 4.117 ;
     RECT  5.64 2.915 5.952 4.453 ;
     RECT  20.4 3.925 20.424 4.501 ;
     RECT  21.84 3.875 22.152 4.501 ;
     RECT  8.496 3.539 8.52 4.645 ;
     RECT  8.496 4.645 9.096 4.837 ;
     RECT  10.128 3.819 12.552 4.837 ;
     RECT  23.856 4.115 23.88 4.981 ;
     RECT  8.4 4.837 12.552 5.077 ;
     RECT  19.2 3.371 19.224 5.077 ;
     RECT  20.256 4.501 22.152 5.077 ;
     RECT  13.632 4.117 17.64 5.171 ;
     RECT  2.544 4.261 2.568 5.507 ;
     RECT  19.2 5.077 22.152 5.605 ;
     RECT  4.704 4.453 5.952 5.653 ;
     RECT  7.92 5.077 12.552 5.653 ;
     RECT  13.632 5.171 17.496 5.653 ;
     RECT  18.624 5.605 22.152 5.653 ;
     RECT  23.232 4.981 23.88 5.653 ;
     RECT  0.24 4.011 0.552 5.917 ;
     RECT  0.144 5.917 0.552 6.035 ;
     RECT  25.008 5.653 25.032 6.229 ;
     RECT  7.824 5.653 17.496 6.323 ;
     RECT  25.008 6.229 25.08 6.325 ;
     RECT  26.112 5.077 26.136 6.325 ;
     RECT  25.008 6.325 26.136 6.419 ;
     RECT  4.704 5.653 6.744 6.805 ;
     RECT  18.624 5.653 23.88 6.899 ;
     RECT  3.792 6.805 6.744 7.091 ;
     RECT  18.624 6.899 23.736 7.989 ;
     RECT  9.939 6.323 17.496 8.003 ;
     RECT  18.528 7.989 23.736 8.051 ;
     RECT  9.939 8.003 14.136 8.149 ;
     RECT  7.824 6.323 8.952 8.437 ;
     RECT  9.936 8.149 14.136 8.437 ;
     RECT  0.24 6.035 0.552 8.485 ;
     RECT  4.704 7.091 6.744 8.533 ;
     RECT  4.224 8.533 6.744 8.565 ;
     RECT  25.008 6.419 25.08 8.579 ;
     RECT  0.24 8.485 0.744 9.109 ;
     RECT  3.936 8.565 6.744 9.109 ;
     RECT  25.056 8.579 25.08 9.109 ;
     RECT  26.112 6.419 26.136 9.109 ;
     RECT  0.24 9.109 1.128 9.205 ;
     RECT  3.408 9.109 6.744 9.637 ;
     RECT  7.824 8.437 14.136 9.637 ;
     RECT  15.168 8.003 17.496 9.637 ;
     RECT  0.24 9.205 1.944 9.685 ;
     RECT  3.408 9.637 17.496 9.685 ;
     RECT  0.24 9.685 17.496 10.213 ;
     RECT  18.624 8.051 23.736 10.213 ;
     RECT  0.24 10.213 23.736 10.261 ;
     RECT  25.056 9.109 26.136 10.261 ;
     RECT  0.24 10.261 26.136 10.837 ;
     RECT  27.24 0.787 27.552 10.837 ;
     RECT  0.24 10.837 27.552 11.093 ;
     RECT  0.24 11.093 27.36 11.363 ;
     RECT  0.384 11.363 26.328 11.728 ;
     RECT  10.032 11.728 10.056 11.795 ;
    LAYER M6 ;
     RECT  0.949 10.816 1.131 10.848 ;
     RECT  1.077 3.968 1.139 4 ;
     RECT  1.669 2.816 1.907 3.488 ;
     RECT  1.907 2.816 2.773 2.848 ;
     RECT  2.805 0.192 2.915 0.224 ;
     RECT  2.773 1.728 3.829 2.848 ;
     RECT  3.829 1.664 3.883 2.912 ;
     RECT  3.925 8.576 4.011 8.608 ;
     RECT  3.883 1.664 4.019 2.848 ;
     RECT  4.405 0.192 4.459 0.224 ;
     RECT  4.019 2.304 4.931 2.72 ;
     RECT  4.931 2.304 5.429 2.336 ;
     RECT  5.413 8 5.483 8.032 ;
     RECT  5.621 0.64 5.891 0.672 ;
     RECT  5.429 2.24 7.189 2.336 ;
     RECT  7.189 1.536 7.221 2.336 ;
     RECT  7.221 1.536 7.333 2.528 ;
     RECT  6.901 0.192 7.349 0.224 ;
     RECT  7.333 1.536 7.349 2.912 ;
     RECT  7.349 0.192 7.523 2.912 ;
     RECT  7.523 0.192 7.531 0.8 ;
     RECT  7.523 2.24 7.717 2.912 ;
     RECT  7.717 2.24 7.787 3.488 ;
     RECT  7.787 2.24 8.003 2.912 ;
     RECT  8.003 2.752 8.555 2.912 ;
     RECT  8.555 2.752 8.579 2.784 ;
     RECT  7.531 0.768 9.203 0.8 ;
     RECT  10.213 3.84 12.035 3.872 ;
     RECT  12.469 2.88 12.523 3.808 ;
     RECT  12.469 0.768 12.659 0.8 ;
     RECT  12.523 3.776 13.379 3.808 ;
     RECT  14.709 3.776 14.915 3.808 ;
     RECT  14.773 2.304 15.253 2.336 ;
     RECT  14.773 0.192 15.349 0.224 ;
     RECT  15.253 2.304 15.349 3.104 ;
     RECT  15.349 0.192 15.541 0.8 ;
     RECT  15.349 2.24 15.541 3.104 ;
     RECT  15.541 0.192 15.787 3.104 ;
     RECT  15.787 0.768 16.019 3.104 ;
     RECT  0 5.364 17.013 6.228 ;
     RECT  17.013 4.544 17.075 6.228 ;
     RECT  16.019 0.768 17.333 0.8 ;
     RECT  16.019 2.24 17.333 2.848 ;
     RECT  17.333 0.768 17.411 2.976 ;
     RECT  17.461 4.032 17.555 4.064 ;
     RECT  17.411 0.768 17.589 1.76 ;
     RECT  17.589 0.192 17.699 1.76 ;
     RECT  17.699 0.96 18.131 1.76 ;
     RECT  18.517 8 18.603 8.032 ;
     RECT  18.131 1.088 18.741 1.76 ;
     RECT  18.741 1.088 19.317 2.912 ;
     RECT  19.317 1.088 19.571 3.36 ;
     RECT  19.571 1.088 19.573 2.912 ;
     RECT  19.573 0.192 19.627 2.912 ;
     RECT  19.627 2.88 19.947 2.912 ;
     RECT  19.627 1.088 20.003 1.12 ;
     RECT  21.621 0.704 21.683 0.736 ;
     RECT  21.621 2.88 22.741 2.912 ;
     RECT  22.741 2.88 22.837 3.36 ;
     RECT  22.837 0.192 22.891 0.672 ;
     RECT  22.837 2.304 22.901 3.36 ;
     RECT  22.891 0.64 23.029 0.672 ;
     RECT  23.029 0.64 23.285 0.928 ;
     RECT  22.901 2.304 23.285 3.488 ;
     RECT  23.285 0.64 23.861 3.488 ;
     RECT  23.861 0.64 23.987 4.064 ;
     RECT  23.987 1.088 24.171 3.488 ;
     RECT  24.171 2.24 24.427 3.488 ;
     RECT  24.427 2.304 24.563 3.488 ;
     RECT  24.563 2.304 25.323 2.336 ;
     RECT  25.269 0.192 25.379 0.224 ;
     RECT  17.075 5.364 25.429 6.228 ;
     RECT  25.429 5.364 25.515 6.368 ;
     RECT  25.461 3.84 25.523 3.872 ;
     RECT  25.515 5.364 28.08 6.228 ;
    LAYER M7 ;
     RECT  4.416 0.181 4.448 0.629 ;
     RECT  6.912 0.181 7.52 0.629 ;
     RECT  22.848 0.181 22.88 0.629 ;
     RECT  22.848 0.629 22.944 0.693 ;
     RECT  4.416 0.629 7.52 0.757 ;
     RECT  14.784 0.181 15.776 0.757 ;
     RECT  17.6 0.181 17.632 0.757 ;
     RECT  21.632 0.693 22.944 0.757 ;
     RECT  21.632 0.757 23.2 1.013 ;
     RECT  14.784 0.757 17.632 1.077 ;
     RECT  19.584 0.181 19.616 1.077 ;
     RECT  21.632 1.013 23.328 1.077 ;
     RECT  25.28 0.181 25.312 1.077 ;
     RECT  2.816 0.181 2.848 1.653 ;
     RECT  4.416 0.757 8.544 1.653 ;
     RECT  2.816 1.653 8.544 1.771 ;
     RECT  3.84 1.771 8.544 2.347 ;
     RECT  14.784 1.077 19.936 2.347 ;
     RECT  21.632 1.077 25.312 2.347 ;
     RECT  7.232 2.347 8.544 2.539 ;
     RECT  3.84 2.347 4 2.923 ;
     RECT  7.36 2.539 8.544 2.923 ;
     RECT  12.48 0.757 12.512 2.923 ;
     RECT  15.296 2.347 19.936 2.923 ;
     RECT  21.632 2.347 24.416 2.923 ;
     RECT  15.296 2.923 19.36 3.115 ;
     RECT  1.856 2.805 1.888 3.499 ;
     RECT  7.744 2.923 7.904 3.499 ;
     RECT  22.912 2.923 24.416 3.499 ;
     RECT  17.024 3.115 19.36 4.075 ;
     RECT  23.872 3.499 23.904 4.075 ;
     RECT  17.024 4.075 17.056 4.587 ;
     RECT  7.872 3.499 7.904 5.803 ;
     RECT  13.056 3.765 13.088 5.803 ;
     RECT  14.72 3.765 14.752 5.803 ;
     RECT  18.56 4.075 19.36 5.803 ;
     RECT  25.472 3.829 25.504 6.379 ;
     RECT  5.44 2.347 5.472 8.043 ;
     RECT  18.56 5.803 18.592 8.043 ;
     RECT  3.968 2.923 4 8.619 ;
     RECT  1.088 3.957 1.12 10.859 ;
  END
END ot_attn_bank_sn136
END LIBRARY
